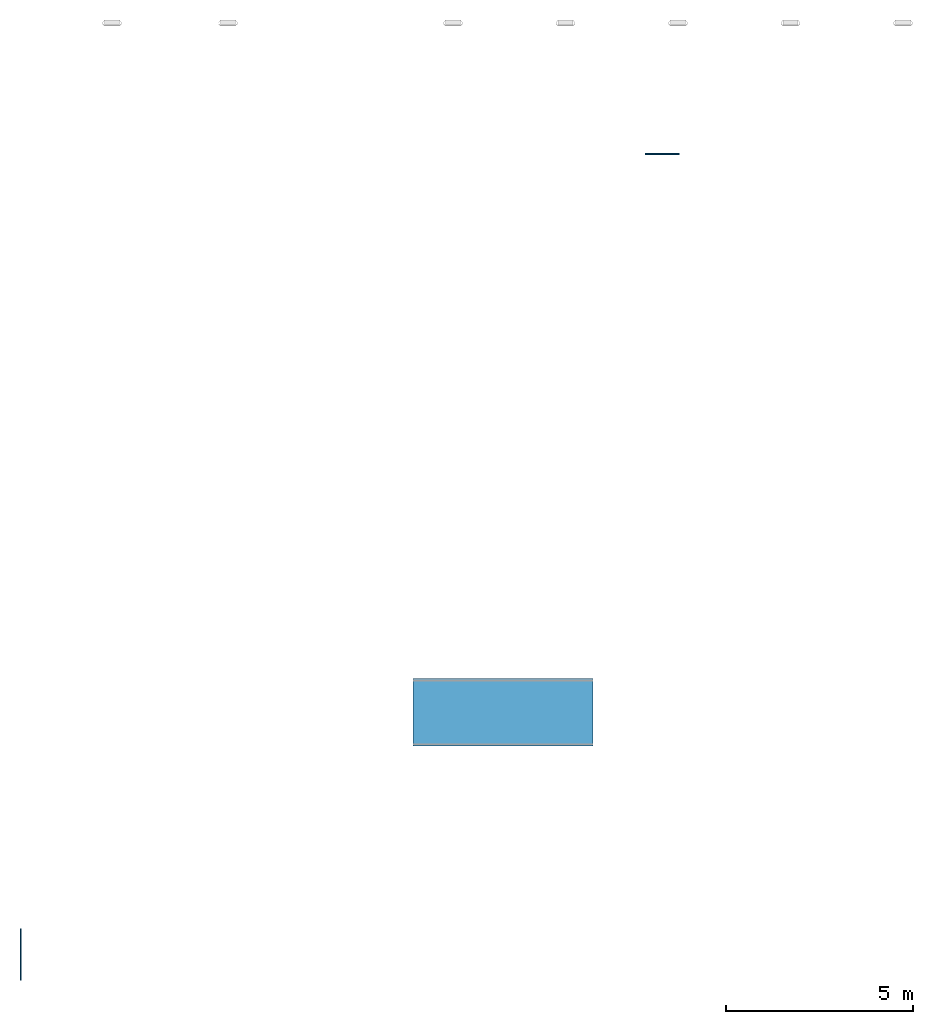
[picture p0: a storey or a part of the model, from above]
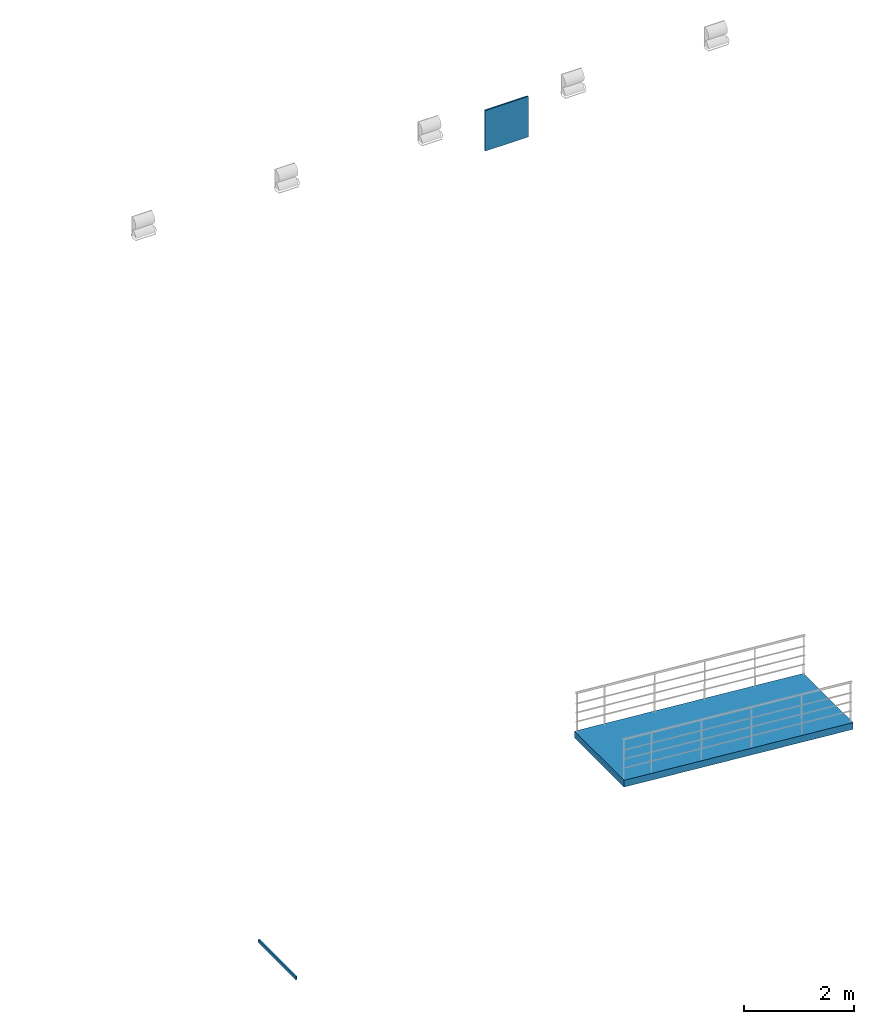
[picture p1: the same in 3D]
Properties of the parts of a building model (IFC2X3), part 1 of 2

# File
Description: ViewDefinition [CoordinationView_V2.0]
File name: 04
Time: 2021-05-14T01:04:37
Written by: The EXPRESS Data Manager Version 5.02.0100.07 : 28 Aug 2013
Made in: 20180216_1515(x64) - Exporter 19.0.0.405 - IU alternativa 19.0.0.405
Comment: STEP Physical File produced by: The EXPRESS Data Manager Version 5.02.0100.07 : 28 Aug 2013 * Module: EDMstepFileFactory/EDMstandAlone * Creation date: Fri May 14 01:04:37 2021 * Host: LAPTOP-GIKO4DUL * Database: C:\Users\MARIAT~1\AppData\Local\Temp\{2545EC60-F883-4820-98E2-E40E6828F80A}\ifc * Database version: 5507 * Database creation date: Fri May 14 01:04:12 2021 * Schema: IFC2X3 * Model: DataRepository.ifc * Model creation date: Fri May 14 01:04:12 2021 * Header model: DataRepository.ifc_HeaderModel * Header model creation date: Fri May 14 01:04:12 2021 * EDMuser: sdai-user * EDMgroup: sdai-group * License ID and type: 5605 : Permanent license. Expiry date: * EDMstepFileFactory options: 020000

# IfcProject, 04
LongName: CURSO REVIT ARCHITECTURE 2015; Phase: Projeto Básico

# IfcSite, Default
RefLatitude: -7, -6, -57, -999999; RefLongitude: -34, -53, -12, -999999; RefElevation: 0 m

# IfcBuilding, C. C. L. Monsenhor Antônio Sampaio
LongName: C. C. L. Monsenhor Antônio Sampaio
Pset_BuildingCommon - NumberOfStoreys: 4

# IfcBuildingStorey (4)
In: C. C. L. Monsenhor Antônio Sampaio
Name | LongName | Elevation (m)
Nível 0 | Nível 0 | -1.18033e-13
Nível 0.8 | Nível 0.8 | 0.8
Nível 1.2 | Nível 1.2 | 1.2
COBERTURA BLOCO 01 | COBERTURA BLOCO 01 | 4.3

# IfcSpace (32)
InteriorOrExteriorSpace: INTERNAL
Name | In | LongName | Reference | CeilingCovering | WallCovering | FloorCovering
57 | Nível 0 | Área | Área 57 | Group: Gross Building
58 | Nível 1.2 | Área | Área 58 | Group: Gross Building
77 | Nível 1.2 | SALA DE AULA 01 | SALA DE AULA 01 77 | 1 | 1 | 1
78 | Nível 1.2 | DIRETORIA | DIRETORIA 78 | 1 | 1 | 1
79 | Nível 1.2 | SECRETARIA | SECRETARIA 79 | 1 | 1 | 1
80 | Nível 1.2 | SALA DE AULA 03 | SALA DE AULA 03 80 | 1 | 1 | 1
81 | Nível 1.2 | SALA DE AULA 04 | SALA DE AULA 04 81 | 1 | 1 | 1
82 | Nível 1.2 | SALA DE AULA 02 | SALA DE AULA 02 82 | 1 | 1 | 1
83 | Nível 1.2 | SALA DE MEDIAÇÃO TECNOLÓGICA | SALA DE MEDIAÇÃO TECNOLÓGICA 83 | 1 | 1 | 2
85 | Nível 1.2 | SALA DE AULA 05 | SALA DE AULA 05 85 | 1 | 1 | 1
86 | Nível 1.2 | BWC FUNC. | BWC FUNC. 86 | 2 | 2 | 1
87 | Nível 1.2 | DML | DML 87 | 2 | 2 | 1
89 | Nível 1.2 | SALA DE INFORMÁTICA | SALA DE INFORMÁTICA 89 | 1 | 1 | 2
90 | Nível 1.2 | COZINHA | COZINHA 90 | 2 | 2 | 1
91 | Nível 1.2 | DEPÓSITO | DEPÓSITO 91 | 2 | 3 | 1
92 | Nível 1.2 | BWC MASC. | BWC MASC. 92 | 2 | 2 | 1
93 | Nível 1.2 | BWC FEM. | BWC FEM. 93 | 2 | 2 | 1
94 | Nível 1.2 | AUDITÓRIO | AUDITÓRIO 94 | 1 | 1 | 2
95 | Nível 1.2 | PCD M. | PCD M. 95 | 2 | 2 | 1
96 | Nível 1.2 | PCD F. | PCD F. 96 | 2 | 2 | 1
98 | Nível 1.2 | BWC M. | BWC M. 98 | 2 | 2 | 1
99 | Nível 1.2 | BWC F. | BWC F. 99 | 2 | 2 | 1
100 | Nível 1.2 | HALL | HALL 100 | 1 | 1 | 1
101 | Nível 1.2 | CIRCULAÇÃO 01 | CIRCULAÇÃO 01 101 | 1 | 1 | 1
102 | Nível 1.2 | CIRC. 02 | CIRC. 02 102 | 1
103 | Nível 1.2 | CIRC. 03 | CIRC. 03 103
104 | Nível 1.2 | PÁTIO ABERTO | PÁTIO ABERTO 104 | 3 | 4
108 | Nível 1.2 | JARDIM | JARDIM 108
110 | Nível 1.2 | LIXO | LIXO 110 | 2 | 2 | 1
116 | Nível 1.2 | HALL AUDITÓRIO | HALL AUDITÓRIO 116
117 | Nível 1.2 | CORREDOR EXTERNO | CORREDOR EXTERNO 117 | 4 | 4
118 | Nível 1.2 | ÁREA EXTERNA | ÁREA EXTERNA 118 | 3 | 4

# IfcBuildingElementProxy: 2000 Litros, Cisterna:2000 Litros:4462246
In: Nível 1.2
Type - Material: Polietileno
Pset_BuildingElementProxyCommon - Reference: 2000 Litros
Pset_ManufacturerTypeInformation - Manufacturer: Fortlev

# IfcBuildingElementProxy: ASYG07-14KMTB (21)
Type - Material: Plastic - Fujitsu General - VR-II - White
Pset_BuildingElementProxyCommon - Reference: ASYG07-14KMTB
Pset_ManufacturerTypeInformation - Manufacturer: FUJITSU GENERAL LIMITED
Name (SPLIT_menor:ASYG07-14KMTB:...) | In
4409967 | 101
4411720 | 79
4411962 | 79
4412251 | 101
4412547 | 101
4412678 | 104
4412776 | 104
4413141 | 101
4413718 | 101
4413755 | 78
4413810 | 78
4413875 | 101
4413943 | 86
4413980 | 117
4414288 | 117
4414644 | 117
4414756 | 117
4414872 | 117
4414974 | 118
4415056 | 118
4460563 | 101

# IfcBuildingElementProxy: Geladeira Inverse Frost Free 422 litros BRE50 - Inox, Geladeira Inverse Frost Free 422 litros BRE50 - Inox:Geladeira Inverse Frost Free 422 litros BRE50 - Inox:4298330
In: 90
Type - Material: Vidro, Inox, Alumínio, Plástico Cinza
Pset_BuildingElementProxyCommon - Reference: Geladeira Inverse Frost Free 422 litros BRE50 - Inox
Pset_ManufacturerTypeInformation - Manufacturer: Brastemp

# IfcBuildingElementProxy: M_Parking Symbol - ADA (2)
In: 94
Material: Paint - White
Pset_BuildingElementProxyCommon - Reference: M_Parking Symbol - ADA
Name (M_Parking Symbol - ADA:M_Parking Symbol - ADA:...)
4352313
4352314

# IfcBuildingElementProxy: Samsung_C8000_UN55C8000_55_3D_LED_10171 (2)
In: 83
Type - Material: Samsung C8000 UN55C8000 55"_LOGO, Samsung C8000 UN55C8000 55"_METAL, Samsung C8000 UN55C8000 55"_FIBERGLASS, Samsung C8000 UN55C8000 55"_SCREEN
Pset_BuildingElementProxyCommon - Reference: Samsung_C8000_UN55C8000_55_3D_LED_10171
Name (Samsung_C8000_UN55C8000_55_3D_LED_10171:Samsung_C8000_UN55C8000_55_3D_LED_10171:...)
4340818
4340819

# IfcBuildingElementProxy: Texto do modelo:280mm Arial
In: COBERTURA BLOCO 01
Pset_BuildingElementProxyCommon - Reference: 280mm Arial

# IfcBuildingElementProxy: Árvore menor - 3 metros (3)
In: Nível 1.2
Pset_BuildingElementProxyCommon - Reference: Árvore menor - 3 metros
Name (RPC Árvore - Tropical:Árvore menor - 3 metros:...)
4311700
4314249
4314272

# IfcColumn: d. 20cm (6)
In: Nível 1.2
Type - ElementType: d. 20cm; PredefinedType: COLUMN
Pset_ColumnCommon - IsExternal: no; Reference: d. 20cm; LoadBearing: yes
Name (Pilar circular:d. 20cm:...)
4174025 | Pset_ColumnCommon - Slope: 0 deg
4174095 | Pset_ColumnCommon - Slope: 0 deg
4174138
4174175
4174350
4174637

# IfcCovering: Forro composto:Forro Mineral (3)
PredefinedType: CEILING; Material: .Forro em gesso 0.03 m
Pset_CoveringCommon - Reference: Forro Mineral; TotalThickness: 0.03 m
Name (Forro composto:Forro Mineral:...) | In
4361125 | 83
4361229 | 89
4361289 | 94

# IfcCovering: Forro composto:Forro de Gesso (20)
PredefinedType: CEILING; Material: .Placa de Gesso Pintada de Branco 0.03 m
Pset_CoveringCommon - Reference: Forro de Gesso; TotalThickness: 0.03 m
Name (Forro composto:Forro de Gesso:...) | In
4361105 | 77
4361117 | 82
4361133 | 78
4361141 | 79
4361189 | 80
4361197 | 81
4361213 | 85
4361237 | 90
4361245 | 91
4361253 | 92
4361263 | 95
4361271 | 93
4361281 | 96
4361297 | 98
4361305 | 99
4361413 | 87
4361421 | 86
4361437 | Nível 1.2
4361453 | Nível 1.2
4399040 | 110

# IfcDoor: 90 x 211 AZUL (21)
Type - ParameterTakesPrecedence: no; Sizeable: no; Material: Pintura Azul
OverallHeight: 2.1 m; OverallWidth: 0.9 m
Pset_DoorCommon - IsExternal: no; Reference: 90 x 211 AZUL; ThermalTransmittance: 3.7021 kg/K/s3
Name (Porta levantamento:90 x 211 AZUL:...) | In
4220187 | Nível 1.2
4220721 | Nível 1.2
4221403 | Nível 1.2
4221503 | Nível 1.2
4222283 | Nível 1.2
4222623 | Nível 1.2
4223136 | Nível 1.2
4224336 | Nível 1.2
4224835 | Nível 1.2
4224943 | Nível 1.2
4225145 | Nível 1.2
4225239 | Nível 1.2
4225373 | Nível 1.2
4225458 | Nível 1.2
4225538 | Nível 1.2
4225822 | Nível 1.2
4307124 | Nível 1.2
4307657 | Nível 1.2
4353306 | Nível 1.2
4400503 | Nível 0.8
4400869 | Nível 0.8

# IfcDoor: AUDITÓRIO azul, Porta dupla auditorio:AUDITÓRIO azul:3969656
In: Nível 1.2
Type - ParameterTakesPrecedence: no; Sizeable: no; Material: Pintura Azul, .Vidro transparente, door panel
OverallHeight: 2.05 m; OverallWidth: 1.85 m
Pset_DoorCommon - IsExternal: no; Reference: AUDITÓRIO azul

# IfcDoor: LIXEIRA E CASA DE GÁS (2)
In: Nível 1.2
Type - ParameterTakesPrecedence: no; Sizeable: no; Material: Alumínio - Pintura eletrostática branca
OverallHeight: 2.16 m; OverallWidth: 0.88 m
Pset_DoorCommon - IsExternal: no; Reference: LIXEIRA E CASA DE GÁS
Pset_ManufacturerTypeInformation - Manufacturer: Sasazaki
Name (Porta de abrir com veneziana ventilada - PAVV:LIXEIRA E CASA DE GÁS:...)
4394019
4396577

# IfcDoor: PORTA BOXE BANHEIROS (3)
In: Nível 1.2
Type - OperationType: SINGLE_SWING_LEFT; ParameterTakesPrecedence: no; Sizeable: no; Classification: 05.01.050 (Uniformat); Material: Padrão, .Madeira, Alumínio
Type - Porta 60x165-15:PORTA BOXE BANHEIROS:4277022 - PanelOperation: SWINGING
OverallHeight: 1.8 m; OverallWidth: 0.744793 m
Pset_DoorCommon - IsExternal: no; Reference: PORTA BOXE BANHEIROS
Name (Porta 60x165-15:PORTA BOXE BANHEIROS:...)
4277022
4277023
4277024

# IfcDoor: PORTA BOXE BANHEIROS (3)
In: Nível 1.2
Type - OperationType: SINGLE_SWING_RIGHT; ParameterTakesPrecedence: no; Sizeable: no; Classification: 05.01.050 (Uniformat); Material: Padrão, .Madeira, Alumínio
Type - Porta 60x165-15:PORTA BOXE BANHEIROS:4276989 - PanelOperation: SWINGING
OverallHeight: 1.8 m; OverallWidth: 0.744793 m
Pset_DoorCommon - IsExternal: no; Reference: PORTA BOXE BANHEIROS
Name (Porta 60x165-15:PORTA BOXE BANHEIROS:...)
4276989
4276990
4276991

# IfcDoor: PORTA DE ENTRADA 3m, Porta pivotante dupla sem revestimento:PORTA DE ENTRADA 3m:3965441
In: Nível 1.2
Type - ParameterTakesPrecedence: no; Sizeable: no; Material: .Alumínio Azul
OverallHeight: 3.1 m; OverallWidth: 1.4 m
Pset_DoorCommon - Reference: PORTA DE ENTRADA 3m; IsExternal: yes; ThermalTransmittance: 3.7021 kg/K/s3

# IfcFlowTerminal: 1994.C.CT_Cromado CR10, Chuveiro:1994.C.CT_Cromado CR10:4299063
In: 86
Classification: D2020 Domestic Water Distribution (Uniformat); Material: Deca CR10 Cromado Metal
Pset_ManufacturerTypeInformation - Manufacturer: Deca
Pset_DistributionFlowElementCommon - Reference: 1994.C.CT_Cromado CR10

# IfcFlowTerminal: 455 x 360 x 850mm (2)
In: 100
Pset_DistributionFlowElementCommon - Reference: 455 x 360 x 850mm
Name (Pia de parede:455 x 360 x 850mm:...)
4408259
4419486

# IfcFlowTerminal: ANMX309 (10)
Type - PredefinedType: SANITARYFOUNTAIN; Material: Aço inoxidável, escovado
Pset_ManufacturerTypeInformation - ModelReference: Drinking Fountain_ANMX309; Manufacturer: ws-info.uk@franke.com
Pset_DistributionFlowElementCommon - Reference: ANMX309
Name (NBS_FrankeSissonsLtd_DrnkngFntnPckgs_DrinkingFountain_ANMX309:ANMX309:...) | In
4391114 | 101
4391115 | 101
4391116 | 101
4393749 | 103
4393750 | 103
4393751 | 103
4393813 | 103
4393814 | 103
4393815 | 103
4393923 | 101

# IfcFlowTerminal: Assento para Bacia Sanitária (9)
Classification: D2010110 Water Closets - Single (Uniformat); Material: Deca GE17 Branco Gelo Plástico
Pset_ManufacturerTypeInformation - Manufacturer: Deca
Pset_DistributionFlowElementCommon - Reference: Assento para Bacia Sanitária
Name (Assento para Bacia Sanitária:Assento para Bacia Sanitária:...) | In
4280281 | 92
4280360 | 92
4280666 | 92
4281077 | 93
4281081 | 93
4281084 | 93
4299518 | 86
4305914 | 99
4307576 | 98

# IfcFlowTerminal: BCS460 W16L124 1xLED24/840 MLO-PC (76)
Type - Material: glass - blue - t85, metal - aluminium
Pset_ManufacturerTypeInformation - Manufacturer: Philips
Pset_DistributionFlowElementCommon - Reference: BCS460 W16L124 1xLED24/840 MLO-PC
Name (63_PHILIPS_smartform-LED-surface_f:BCS460 W16L124 1xLED24/840 MLO-PC:...) | In
4367687 | 81
4367688 | 81
4367689 | 81
4367690 | 81
4370990 | 81
4370991 | 81
4371206 | 80
4371207 | 80
4371208 | 80
4371209 | 80
4371211 | 80
4371212 | 80
4371623 | 77
4371624 | 77
4371625 | 77
4371626 | 77
4371627 | 77
4371628 | 77
4371737 | 82
4371738 | 82
4371739 | 82
4371740 | 82
4371742 | 82
4371743 | 82
4371914 | 83
4371915 | 83
4371916 | 83
4371917 | 83
4371918 | 83
4371919 | 83
4372436 | 89
4372437 | 89
4372438 | 89
4372439 | 89
4372440 | 89
4372441 | 89
4372748 | 90
4372749 | 90
4372750 | 90
4373002 | 94
4373003 | 94
4373210 | 94
4373211 | 94
4373272 | 94
4373273 | 94
4373290 | 94
4373291 | 94
4373303 | 94
4373304 | 94
4373317 | 94
4373318 | 94
4373326 | 94
4373327 | 94
4373403 | Nível 1.2
4373404 | Nível 1.2
4373625 | 85
4373628 | 85
4373744 | 85
4373745 | 85
4387714 | 100
4387939 | 101
4388071 | 101
4388201 | 101
4388233 | 101
4388684 | 92
4388706 | 93
4389699 | 92
4389745 | 93
4390718 | 103
4390791 | 103
4390823 | 103
4390860 | 102
4390928 | 102
4391031 | 102
4398995 | 102
4398996 | 102

# IfcFlowTerminal: BR03_ConjuntoLavatórioeBaciaAcessíveis_ComVálvulaDeDescarga_DN32mm(1 1/4") (2)
Classification: 08.16.091 (Uniformat); Material: FDE_AçoCromado, FDE_CerâmicaEsmaltadaBranca, FDE_ResinaPosliéster (Branco), FDE_AçoInox
Pset_DistributionFlowElementCommon - Reference: BR03_ConjuntoLavatórioeBaciaAcessíveis_ComVálvulaDeDescarga_DN32mm(1 1/4")
Name (FDE_BR03_ConjuntoLavatórioeBaciaAcessíveis:BR03_ConjuntoLavatórioeBaciaAcessíveis_ComVálvulaDeDescarga_DN32mm(1 1/4"):...) | In
4292054 | 95
4293119 | 96

# IfcFlowTerminal: CT.25_Branco Gelo GE17, Deca_Shared_Coluna para Tanque_TQ.03:CT.25_Branco Gelo GE17:4334062
In: Nível 1.2
Classification: D2010400 Sinks (Uniformat); Material: Deca GE17 Branco Gelo Cerâmica
Pset_ManufacturerTypeInformation - Manufacturer: Deca
Pset_DistributionFlowElementCommon - Reference: CT.25_Branco Gelo GE17

# IfcFlowTerminal: Caixa de Descarga Acoplada (9)
Classification: D2010110 Water Closets - Single (Uniformat); Material: Deca CR37 Creme Cerâmica
Pset_ManufacturerTypeInformation - Manufacturer: CD.00.17
Pset_DistributionFlowElementCommon - Reference: Caixa de Descarga Acoplada
Name (Caixa de Descarga Acoplada:Caixa de Descarga Acoplada:...) | In
4280282 | 92
4280361 | 92
4280667 | 92
4281078 | 93
4281082 | 93
4281085 | 93
4299519 | 86
4305915 | 99
4307577 | 98

# IfcFlowTerminal: Cuba 40x70 (2)
In: 90
Material: Stainless Steel
Pset_ManufacturerTypeInformation - Manufacturer: CABRO
Pset_DistributionFlowElementCommon - Reference: Cuba 40x70
Name (Cuba_Cozinha1:Cuba 40x70:...)
4297387
4297388

# IfcFlowTerminal: H613_RestritorDeVazãoPara6L/minTorneiraseMisturadores (2)
Classification: 08.17.078 (Uniformat)
Pset_DistributionFlowElementCommon - Reference: H613_RestritorDeVazãoPara6L/minTorneiraseMisturadores
Name (FDE_H613_DispositivosRestritoresDeVazão:H613_RestritorDeVazãoPara6L/minTorneiraseMisturadores:...) | In
4292057 | 95
4293122 | 96

# IfcFlowTerminal: IL63_4x16W-40x40 (10)
In: Nível 1.2
Type - Classification: 09.09.063 (Uniformat); Material: Aço com Acabamento em Pintura Eletrostática em Pó Branca, Lâmpada Fluorescente, Policarbonato, Alumínio Anodizado Polido
Pset_DistributionFlowElementCommon - Reference: IL63_4x16W-40x40
Name (FDE_IL63_LumináriaInterna_LumináriadeEmbutir_comRefletoreAletas:IL63_4x16W-40x40:...)
4386625
4386684
4386753
4386830
4386903
4386990
4387107
4387216
4387559
4399196

# IfcFlowTerminal: IL84_1x150W_opção1 (2)
Type - Classification: 09.11.076 (Uniformat); Material: Alumínio Anodizado Brilhante, Lâmpada de Vapor de Sódio, Porcelana, Vidro Temperado, Aço galvanizado
Pset_DistributionFlowElementCommon - Reference: IL84_1x150W_opção1
Name (FDE_IL84_LumináriaExterna_Projetor_opção1:IL84_1x150W_opção1:...) | In
4402668 | 108
4408045 | Nível 1.2

# IfcFlowTerminal: IL85_1x250W_opção2 (7)
In: Nível 0
Type - Classification: 09.11.077 (Uniformat); Material: Lâmpada de Vapor de Sódio, Porcelana, Alumínio Anodizado Brilhante, Vidro Temperado, Aço galvanizado
Pset_DistributionFlowElementCommon - Reference: IL85_1x250W_opção2
Name (FDE_IL85_LumináriaExterna_Projetor_opção2:IL85_1x250W_opção2:...)
4403228
4403448
4403821
4403822
4403885
4403909
4403936

# IfcFlowTerminal: L.37.17_Branco Gelo GE17 (9)
Classification: D2010400 Sinks (Uniformat); Material: Deca GE17 Branco Gelo Cerâmica
Pset_ManufacturerTypeInformation - Manufacturer: Deca
Pset_DistributionFlowElementCommon - Reference: L.37.17_Branco Gelo GE17
Name (Cuba Oval de Embutir1:L.37.17_Branco Gelo GE17:...) | In
4277048 | 93
4277050 | 93
4277202 | 93
4277747 | 92
4277749 | 92
4277750 | 92
4300827 | 86
4304887 | 99
4307573 | 98

# IfcFlowTerminal: Lavatório Top (6)
Material: Cromado - Docol
Pset_ManufacturerTypeInformation - Manufacturer: Docol
Pset_DistributionFlowElementCommon - Reference: Lavatório Top
Name (Sifao para lavatorio - DocolBasicos:Lavatório Top:...) | In
4277647 | 93
4277701 | 93
4277722 | 93
4277751 | 92
4277752 | 92
4277753 | 92

# IfcFlowTerminal: P.750_Creme CR37_Acionamento Simples 6lpf (9)
Classification: D2010110 Water Closets - Single (Uniformat); Material: Deca CR37 Creme Cerâmica
Pset_ManufacturerTypeInformation - Manufacturer: Deca
Pset_DistributionFlowElementCommon - Reference: P.750_Creme CR37_Acionamento Simples 6lpf
Name (Bacia para Caixa Acoplada:P.750_Creme CR37_Acionamento Simples 6lpf:...) | In
4280279 | 92
4280358 | 92
4280664 | 92
4281076 | 93
4281080 | 93
4281083 | 93
4299516 | 86
4305912 | 99
4307575 | 98

# IfcFlowTerminal: Poste de iluminação - Redondo (18)
Type - Material: Metal - Cromo, Vidro, Branco, Alta Luminosidade, Metal - Alum
Pset_DistributionFlowElementCommon - Reference: Poste de iluminação - Redondo
Name (Poste de iluminação - Redondo:Poste de iluminação - Redondo:...) | In
4399500 | 104
4401171 | 104
4404501 | 104
4404594 | 104
4405208 | 104
4405645 | 104
4406009 | 118
4406144 | 118
4407786 | 118
4408570 | 117
4408571 | 117
4408572 | 117
4408573 | 117
4408574 | 117
4408575 | 117
4408576 | 117
4408577 | 117
4408923 | 104

# IfcFlowTerminal: TQ.03_Branco Gelo GE17, Deca_Tanque_TQ.03_40 Litros:TQ.03_Branco Gelo GE17:4334060
In: Nível 1.2
Classification: D2010400 Sinks (Uniformat); Material: Deca GE17 Branco Gelo Cerâmica
Pset_ManufacturerTypeInformation - Manufacturer: Deca
Pset_DistributionFlowElementCommon - Reference: TQ.03_Branco Gelo GE17

# IfcFlowTerminal: Torneira 1 (4)
In: 100
Pset_DistributionFlowElementCommon - Reference: Torneira 1
Name (Torneira 1:Torneira 1:...)
4408260
4408261
4419487
4419488

# IfcFlowTerminal: Torneira 3 (2)
In: 100
Pset_DistributionFlowElementCommon - Reference: Torneira 3
Name (Torneira 3:Torneira 3:...)
4408262
4419489

# IfcFurnishingElement: 5-M-SR11-00-E111-A2B-F10001/F193 (5)
Type - ElementType: 5-M-SR11-00-E111-A2B-F10001/F193; Material: Nylon Black, Mesh Black, Black, Silver
Pset_ManufacturerTypeInformation - Manufacturer: Modernform
Name (Cadeira diretoria:5-M-SR11-00-E111-A2B-F10001/F193:...) | In
4348319 | 78
4352126 | 94
4352128 | 94
4352129 | 94
4352130 | 94

# IfcFurnishingElement: 800x800mm, NBS_OffcTbls_RoundTable:800x800mm:4348874
In: 79
Type - ElementType: 800x800mm; Material: Wood - Glue-Laminated
Pset_ManufacturerTypeInformation - ModelReference: Round Table; Manufacturer: info@theNBS.com

# IfcFurnishingElement: Bancada (8)
Type - ElementType: Bancada
Name | In | Group
BancadaL:Bancada:4297389 | 90
Bancada_balcao:Bancada:4345387 | 89 | Grupo de modelos:Bancada Informática:4345391
Bancada_balcao:Bancada:4345395 | 89 | Grupo de modelos:Bancada Informática:4345399
Bancada_balcao:Bancada:4345403 | 89 | Grupo de modelos:Bancada Informática:4345407
Bancada_balcao:Bancada:4345411 | 89 | Grupo de modelos:Bancada Informática:4345415
Bancada_balcao:Bancada:4345419 | 89 | Grupo de modelos:Bancada Informática:4345423
Bancada_balcao:Bancada:4345427 | 89 | Grupo de modelos:Bancada Informática:4345431
Bancada_balcao:Bancada:4345435 | 89 | Grupo de modelos:Bancada Informática:4345439

# IfcFurnishingElement: Bancada_50x320 2 (3)
Type - ElementType: Bancada_50x320 2
Name (Bancada1:Bancada_50x320 2:...) | In
4300014 | 86
4304886 | 99
4307572 | 98

# IfcFurnishingElement: Bancada_L_60x265 (3)
Type - ElementType: Bancada_L_60x265
Name (Bancada1:Bancada_L_60x265:...) | In
4277047 | 93
4277746 | 92
4297386 | 90

# IfcFurnishingElement: Cadeira auditório (90)
In: 94
Type - ElementType: Cadeira auditório; Material: V9 - V9 - Ecopelle_672_658, V9 - V9 - RAL_9006_Grigio
Name
Furniture_Armchairs_Ares-Line_V9:Cadeira auditório:4352305
cadeira auditório pcd:Cadeira auditório:4352309
cadeira auditório pcd:Cadeira auditório:4352310
cadeira auditório pcd:Cadeira auditório:4352311
cadeira auditório pcd:Cadeira auditório:4352315
cadeira auditório pcd:Cadeira auditório:4352316
cadeira auditório pcd:Cadeira auditório:4352317
cadeira auditório pcd:Cadeira auditório:4352318
cadeira auditório pcd:Cadeira auditório:4352430
cadeira auditório pcd:Cadeira auditório:4352431
cadeira auditório pcd:Cadeira auditório:4352516
cadeira auditório pcd:Cadeira auditório:4352517
cadeira auditório pcd:Cadeira auditório:4352527
cadeira auditório pcd:Cadeira auditório:4352528
cadeira auditório pcd:Cadeira auditório:4352529
cadeira auditório pcd:Cadeira auditório:4352530
cadeira auditório pcd:Cadeira auditório:4352531
cadeira auditório pcd:Cadeira auditório:4352532
cadeira auditório pcd:Cadeira auditório:4352972
cadeira auditório pcd:Cadeira auditório:4352973
cadeira auditório pcd:Cadeira auditório:4352974
cadeira auditório pcd:Cadeira auditório:4352975
cadeira auditório pcd:Cadeira auditório:4352976
cadeira auditório pcd:Cadeira auditório:4352977
cadeira auditório pcd:Cadeira auditório:4352978
cadeira auditório pcd:Cadeira auditório:4352979
cadeira auditório pcd:Cadeira auditório:4352980
cadeira auditório pcd:Cadeira auditório:4352981
cadeira auditório pcd:Cadeira auditório:4352982
cadeira auditório pcd:Cadeira auditório:4352983
cadeira auditório pcd:Cadeira auditório:4353070
cadeira auditório pcd:Cadeira auditório:4353071
cadeira auditório pcd:Cadeira auditório:4353072
cadeira auditório pcd:Cadeira auditório:4353073
cadeira auditório pcd:Cadeira auditório:4353074
cadeira auditório pcd:Cadeira auditório:4353075
cadeira auditório pcd:Cadeira auditório:4353076
cadeira auditório pcd:Cadeira auditório:4353077
cadeira auditório pcd:Cadeira auditório:4353078
cadeira auditório pcd:Cadeira auditório:4353079
cadeira auditório pcd:Cadeira auditório:4353080
cadeira auditório pcd:Cadeira auditório:4353081
cadeira auditório pcd:Cadeira auditório:4353100
cadeira auditório pcd:Cadeira auditório:4353101
cadeira auditório pcd:Cadeira auditório:4353102
cadeira auditório pcd:Cadeira auditório:4353103
cadeira auditório pcd:Cadeira auditório:4353104
cadeira auditório pcd:Cadeira auditório:4353105
cadeira auditório pcd:Cadeira auditório:4353106
cadeira auditório pcd:Cadeira auditório:4353107
cadeira auditório pcd:Cadeira auditório:4353108
cadeira auditório pcd:Cadeira auditório:4353109
cadeira auditório pcd:Cadeira auditório:4353110
cadeira auditório pcd:Cadeira auditório:4353111
cadeira auditório pcd:Cadeira auditório:4353119
cadeira auditório pcd:Cadeira auditório:4353120
cadeira auditório pcd:Cadeira auditório:4353121
cadeira auditório pcd:Cadeira auditório:4353122
cadeira auditório pcd:Cadeira auditório:4353123
cadeira auditório pcd:Cadeira auditório:4353124
cadeira auditório pcd:Cadeira auditório:4353125
cadeira auditório pcd:Cadeira auditório:4353126
cadeira auditório pcd:Cadeira auditório:4353127
cadeira auditório pcd:Cadeira auditório:4353128
cadeira auditório pcd:Cadeira auditório:4353129
cadeira auditório pcd:Cadeira auditório:4353130
cadeira auditório pcd:Cadeira auditório:4353151
cadeira auditório pcd:Cadeira auditório:4353152
cadeira auditório pcd:Cadeira auditório:4353153
cadeira auditório pcd:Cadeira auditório:4353154
cadeira auditório pcd:Cadeira auditório:4353155
cadeira auditório pcd:Cadeira auditório:4353156
cadeira auditório pcd:Cadeira auditório:4353157
cadeira auditório pcd:Cadeira auditório:4353158
cadeira auditório pcd:Cadeira auditório:4353159
cadeira auditório pcd:Cadeira auditório:4353160
cadeira auditório pcd:Cadeira auditório:4353161
cadeira auditório pcd:Cadeira auditório:4353162
cadeira auditório pcd:Cadeira auditório:4353172
cadeira auditório pcd:Cadeira auditório:4353173
cadeira auditório pcd:Cadeira auditório:4353174
cadeira auditório pcd:Cadeira auditório:4353175
cadeira auditório pcd:Cadeira auditório:4353176
cadeira auditório pcd:Cadeira auditório:4353177
cadeira auditório pcd:Cadeira auditório:4353178
cadeira auditório pcd:Cadeira auditório:4353179
cadeira auditório pcd:Cadeira auditório:4353180
cadeira auditório pcd:Cadeira auditório:4353181
cadeira auditório pcd:Cadeira auditório:4353182
cadeira auditório pcd:Cadeira auditório:4353183

# IfcFurnishingElement: Cadeira-Breuer (15)
Type - ElementType: Cadeira-Breuer; Material: Tecido - Fibras de bambu, Metal - Cromo
Name | In
Cadeira-Breuer1:Cadeira-Breuer:4339522 | 77
Cadeira-Breuer1:Cadeira-Breuer:4340231 | 80
Cadeira-Breuer1:Cadeira-Breuer:4340532 | 81
Cadeira-Breuer1:Cadeira-Breuer:4340592 | 82
Cadeira-Breuer1:Cadeira-Breuer:4345440 | 89
Cadeira-Breuer1:Cadeira-Breuer:4348317 | 78
Cadeira-Breuer1:Cadeira-Breuer:4348318 | 78
Cadeira-Breuer1:Cadeira-Breuer:4348547 | 79
Cadeira-Breuer1:Cadeira-Breuer:4348549 | 79
Cadeira-Breuer1:Cadeira-Breuer:4348875 | 79
Cadeira-Breuer1:Cadeira-Breuer:4348876 | 79
Cadeira-Breuer1:Cadeira-Breuer:4348877 | 79
Cadeira-Breuer1:Cadeira-Breuer:4348878 | 79
Cadeira-Breuer1:Cadeira-Breuer:4349871 | 85
Cadeira-Breuer:Cadeira-Breuer:4418807 | Nível 0.8

# IfcFurnishingElement: Carteira_Sala de Aula (140)
Type - ElementType: Carteira_Sala de Aula; Classification: E2020200 Furniture & Accessories (Uniformat); Material: Furniture - KI - Chair Glide, Furniture - KI - Chair Frame, Furniture - KI - Tablet, Furniture - KI - Chair Poly
Pset_ManufacturerTypeInformation - Manufacturer: KI
Name (Tablet_Arm_Chair_4-Leg-KI-Strive:Carteira_Sala de Aula:...) | In | Group
4339220 | 77 | Grupo de modelos:CARTEIRAS 2:4339250
4339221 | 77 | Grupo de modelos:CARTEIRAS 2:4339250
4339222 | 77 | Grupo de modelos:CARTEIRAS 2:4339250
4339223 | 77 | Grupo de modelos:CARTEIRAS 2:4339250
4339224 | 77 | Grupo de modelos:CARTEIRAS 2:4339250
4339225 | 77 | Grupo de modelos:CARTEIRAS 2:4339250
4339226 | 77 | Grupo de modelos:CARTEIRAS 2:4339250
4339227 | 77 | Grupo de modelos:CARTEIRAS 2:4339250
4339228 | 77 | Grupo de modelos:CARTEIRAS 2:4339250
4339229 | 77 | Grupo de modelos:CARTEIRAS 2:4339250
4339230 | 77 | Grupo de modelos:CARTEIRAS 2:4339250
4339231 | 77 | Grupo de modelos:CARTEIRAS 2:4339250
4339232 | 77 | Grupo de modelos:CARTEIRAS 2:4339250
4339233 | 77 | Grupo de modelos:CARTEIRAS 2:4339250
4339234 | 77 | Grupo de modelos:CARTEIRAS 2:4339250
4339235 | 77 | Grupo de modelos:CARTEIRAS 2:4339250
4339236 | 77 | Grupo de modelos:CARTEIRAS 2:4339250
4339237 | 77 | Grupo de modelos:CARTEIRAS 2:4339250
4339238 | 77 | Grupo de modelos:CARTEIRAS 2:4339250
4339239 | 77 | Grupo de modelos:CARTEIRAS 2:4339250
4339240 | 77 | Grupo de modelos:CARTEIRAS 2:4339250
4339241 | 77 | Grupo de modelos:CARTEIRAS 2:4339250
4339242 | 77 | Grupo de modelos:CARTEIRAS 2:4339250
4339243 | 77 | Grupo de modelos:CARTEIRAS 2:4339250
4340206 | 80 | Grupo de modelos:CARTEIRAS 2:4340230
4340207 | 80 | Grupo de modelos:CARTEIRAS 2:4340230
4340208 | 80 | Grupo de modelos:CARTEIRAS 2:4340230
4340209 | 80 | Grupo de modelos:CARTEIRAS 2:4340230
4340210 | 80 | Grupo de modelos:CARTEIRAS 2:4340230
4340211 | 80 | Grupo de modelos:CARTEIRAS 2:4340230
4340212 | 80 | Grupo de modelos:CARTEIRAS 2:4340230
4340213 | 80 | Grupo de modelos:CARTEIRAS 2:4340230
4340214 | 80 | Grupo de modelos:CARTEIRAS 2:4340230
4340215 | 80 | Grupo de modelos:CARTEIRAS 2:4340230
4340216 | 80 | Grupo de modelos:CARTEIRAS 2:4340230
4340217 | 80 | Grupo de modelos:CARTEIRAS 2:4340230
4340218 | 80 | Grupo de modelos:CARTEIRAS 2:4340230
4340219 | 80 | Grupo de modelos:CARTEIRAS 2:4340230
4340220 | 80 | Grupo de modelos:CARTEIRAS 2:4340230
4340221 | 80 | Grupo de modelos:CARTEIRAS 2:4340230
4340222 | 80 | Grupo de modelos:CARTEIRAS 2:4340230
4340223 | 80 | Grupo de modelos:CARTEIRAS 2:4340230
4340224 | 80 | Grupo de modelos:CARTEIRAS 2:4340230
4340225 | 80 | Grupo de modelos:CARTEIRAS 2:4340230
4340226 | 80 | Grupo de modelos:CARTEIRAS 2:4340230
4340227 | 80 | Grupo de modelos:CARTEIRAS 2:4340230
4340228 | 80 | Grupo de modelos:CARTEIRAS 2:4340230
4340229 | 80 | Grupo de modelos:CARTEIRAS 2:4340230
4340249 | 81 | Grupo de modelos:CARTEIRAS 2:4340273
4340250 | 81 | Grupo de modelos:CARTEIRAS 2:4340273
4340251 | 81 | Grupo de modelos:CARTEIRAS 2:4340273
4340252 | 81 | Grupo de modelos:CARTEIRAS 2:4340273
4340253 | 81 | Grupo de modelos:CARTEIRAS 2:4340273
4340254 | 81 | Grupo de modelos:CARTEIRAS 2:4340273
4340255 | 81 | Grupo de modelos:CARTEIRAS 2:4340273
4340256 | 81 | Grupo de modelos:CARTEIRAS 2:4340273
4340257 | 81 | Grupo de modelos:CARTEIRAS 2:4340273
4340258 | 81 | Grupo de modelos:CARTEIRAS 2:4340273
4340259 | 81 | Grupo de modelos:CARTEIRAS 2:4340273
4340260 | 81 | Grupo de modelos:CARTEIRAS 2:4340273
4340261 | 81 | Grupo de modelos:CARTEIRAS 2:4340273
4340262 | 81 | Grupo de modelos:CARTEIRAS 2:4340273
4340263 | 81 | Grupo de modelos:CARTEIRAS 2:4340273
4340264 | 81 | Grupo de modelos:CARTEIRAS 2:4340273
4340265 | 81 | Grupo de modelos:CARTEIRAS 2:4340273
4340266 | 81 | Grupo de modelos:CARTEIRAS 2:4340273
4340267 | 81 | Grupo de modelos:CARTEIRAS 2:4340273
4340268 | 81 | Grupo de modelos:CARTEIRAS 2:4340273
4340269 | 81 | Grupo de modelos:CARTEIRAS 2:4340273
4340270 | 81 | Grupo de modelos:CARTEIRAS 2:4340273
4340271 | 81 | Grupo de modelos:CARTEIRAS 2:4340273
4340272 | 81 | Grupo de modelos:CARTEIRAS 2:4340273
4340567 | 82 | Grupo de modelos:CARTEIRAS 2:4340591
4340568 | 82 | Grupo de modelos:CARTEIRAS 2:4340591
4340569 | 82 | Grupo de modelos:CARTEIRAS 2:4340591
4340570 | 82 | Grupo de modelos:CARTEIRAS 2:4340591
4340571 | 82 | Grupo de modelos:CARTEIRAS 2:4340591
4340572 | 82 | Grupo de modelos:CARTEIRAS 2:4340591
4340573 | 82 | Grupo de modelos:CARTEIRAS 2:4340591
4340574 | 82 | Grupo de modelos:CARTEIRAS 2:4340591
4340575 | 82 | Grupo de modelos:CARTEIRAS 2:4340591
4340576 | 82 | Grupo de modelos:CARTEIRAS 2:4340591
4340577 | 82 | Grupo de modelos:CARTEIRAS 2:4340591
4340578 | 82 | Grupo de modelos:CARTEIRAS 2:4340591
4340579 | 82 | Grupo de modelos:CARTEIRAS 2:4340591
4340580 | 82 | Grupo de modelos:CARTEIRAS 2:4340591
4340581 | 82 | Grupo de modelos:CARTEIRAS 2:4340591
4340582 | 82 | Grupo de modelos:CARTEIRAS 2:4340591
4340583 | 82 | Grupo de modelos:CARTEIRAS 2:4340591
4340584 | 82 | Grupo de modelos:CARTEIRAS 2:4340591
4340585 | 82 | Grupo de modelos:CARTEIRAS 2:4340591
4340586 | 82 | Grupo de modelos:CARTEIRAS 2:4340591
4340587 | 82 | Grupo de modelos:CARTEIRAS 2:4340591
4340588 | 82 | Grupo de modelos:CARTEIRAS 2:4340591
4340589 | 82 | Grupo de modelos:CARTEIRAS 2:4340591
4340590 | 82 | Grupo de modelos:CARTEIRAS 2:4340591
4349847 | 85
4349848 | 85
4349849 | 85
4349850 | 85
4349853 | 85
4349854 | 85
4349855 | 85
4349856 | 85
4349860 | 85
4349861 | 85
4349862 | 85
4349866 | 85
4349867 | 85
4349868 | 85
4352042 | 85
4352043 | 85
4352044 | 85
4353527 | 85
4353528 | 85
4353529 | 85
4400800 | 83 | Grupo de modelos:CARTEIRAS 2:4400773
4400801 | 83 | Grupo de modelos:CARTEIRAS 2:4400773
4400802 | 83 | Grupo de modelos:CARTEIRAS 2:4400773
4400803 | 83 | Grupo de modelos:CARTEIRAS 2:4400773
4400804 | 83 | Grupo de modelos:CARTEIRAS 2:4400773
4400805 | 83 | Grupo de modelos:CARTEIRAS 2:4400773
4400806 | 83 | Grupo de modelos:CARTEIRAS 2:4400773
4400807 | 83 | Grupo de modelos:CARTEIRAS 2:4400773
4400808 | 83 | Grupo de modelos:CARTEIRAS 2:4400773
4400809 | 83 | Grupo de modelos:CARTEIRAS 2:4400773
4400810 | 83 | Grupo de modelos:CARTEIRAS 2:4400773
4400811 | 83 | Grupo de modelos:CARTEIRAS 2:4400773
4400812 | 83 | Grupo de modelos:CARTEIRAS 2:4400773
4400813 | 83 | Grupo de modelos:CARTEIRAS 2:4400773
4400814 | 83 | Grupo de modelos:CARTEIRAS 2:4400773
4400815 | 83 | Grupo de modelos:CARTEIRAS 2:4400773
4400816 | 83 | Grupo de modelos:CARTEIRAS 2:4400773
4400817 | 83 | Grupo de modelos:CARTEIRAS 2:4400773
4400818 | 83 | Grupo de modelos:CARTEIRAS 2:4400773
4400819 | 83 | Grupo de modelos:CARTEIRAS 2:4400773
4400820 | 83 | Grupo de modelos:CARTEIRAS 2:4400773
4400821 | 83 | Grupo de modelos:CARTEIRAS 2:4400773
4400822 | 83 | Grupo de modelos:CARTEIRAS 2:4400773
4400823 | 83 | Grupo de modelos:CARTEIRAS 2:4400773

# IfcFurnishingElement: Concrete_Bench_7009 (7)
Type - ElementType: Concrete_Bench_7009; Material: Concrete
Name (Banco Concreto:Concrete_Bench_7009:...) | In
4317291 | 118
4317430 | 118
4317686 | 118
4317687 | 118
4404828 | Nível 0.8
4405083 | 104
4409065 | Nível 0.8

# IfcFurnishingElement: Industrial_Stove_14527, Fogão Industrial:Industrial_Stove_14527:4298373
In: 90
Type - ElementType: Industrial_Stove_14527; Material: Metal - Chrome, Metal - Steel
Pset_ManufacturerTypeInformation - Manufacturer: Generic
Group: Grupo de modelos:Fogão:4298366

# IfcFurnishingElement: Mesa ADM 1.30x.60 (3)
Type - ElementType: Mesa ADM 1.30x.60; Material: Furniture_Watson_Seven_Leg, Furniture_Watson_Seven_Top
Pset_ManufacturerTypeInformation - Manufacturer: Watson Desking
Name (Watson_Seven_Rectangle:Mesa ADM 1.30x.60:...) | In
4348548 | 79
4348550 | 79
4349396 | 78

# IfcFurnishingElement: Mesa ADM 1.50x.60 (7)
Type - ElementType: Mesa ADM 1.50x.60; Material: Furniture_Watson_Seven_Leg, Furniture_Watson_Seven_Top
Pset_ManufacturerTypeInformation - Manufacturer: Watson Desking
Name (Watson_Seven_Rectangle:Mesa ADM 1.50x.60:...) | In
4339524 | 77
4340232 | 80
4340533 | 81
4340593 | 82
4342722 | 83
4345441 | 89
4349872 | 85

# IfcFurnishingElement: Mesa ADM 2.00x.70, Mesa_Escrivaninha:Mesa ADM 2.00x.70:4348316
In: 78
Type - ElementType: Mesa ADM 2.00x.70; Material: Furniture_Watson_Seven_Leg, Furniture_Watson_Seven_Top
Pset_ManufacturerTypeInformation - Manufacturer: Watson Desking

# IfcFurnishingElement: Mesa ADM 5.00x.60, Watson_Seven_Rectangle:Mesa ADM 5.00x.60:4352127
In: 94
Type - ElementType: Mesa ADM 5.00x.60; Material: Furniture_Watson_Seven_Leg, Furniture_Watson_Seven_Top
Pset_ManufacturerTypeInformation - Manufacturer: Watson Desking

# IfcFurnishingElement: Non-Upholstered (21)
In: 89
Type - ElementType: Non-Upholstered; Material: Furniture_Coalesse_Kart - Arm/Back/Seat (Poly), Furniture_Coalesse_Kart - Glide, Furniture_Coalesse_Kart - Flex Bar, Furniture_Coalesse_Kart - Frame
Pset_ManufacturerTypeInformation - Manufacturer: COALESSE
Name (COALESSE_KART_-_Stacking_Chair_8918:Non-Upholstered:...)
4345388
4345389
4345390
4345396
4345397
4345398
4345404
4345405
4345406
4345412
4345413
4345414
4345420
4345421
4345422
4345428
4345429
4345430
4345436
4345437
4345438

# IfcFurnishingElement: Quadro (7)
Type - ElementType: Quadro; Classification: C1030540 Chalkboards & Whiteboards (Uniformat); Material: Frame - Aluminum, Board Material - White Board, Plastic, Grey
Pset_ManufacturerTypeInformation - Manufacturer: Marsh Industries, Inc.
Name (Dry-Erase-Board_Electronic_Marsh:Quadro:...) | In
4339702 | 82
4340233 | 81
4340503 | 80
4340594 | 77
4342206 | Nível 1.2
4347902 | 90
4351990 | 86

# IfcFurnishingElement: Shelving_Unit_-_Fully_Parametric_12010 (8)
Type - ElementType: Shelving_Unit_-_Fully_Parametric_12010
Name (Shelving_Unit_-_Fully_Parametric_12010:Shelving_Unit_-_Fully_Parametric_12010:...) | In
4348551 | 79
4348552 | 79
4348553 | 79
4348838 | 79
4349580 | 78
4349581 | 78
4349582 | 78
4349583 | 78

# IfcFurnishingElement: Three Seater (6)
In: 101
Type - ElementType: Three Seater; Material: Seat Base, Seat Arms, Support Rail
Name (Cadeira Longarina:Three Seater:...)
4349657
4349722
4349752
4349794
4349795
4349796

# IfcMember: 6x5 cm (51)
In: COBERTURA BLOCO 01
Type - ElementType: 6x5 cm; PredefinedType: MEMBER
Material: .Madeira
Pset_MemberCommon - IsExternal: yes; LoadBearing: yes; Reference: 6x5 cm
Name (Rectangular Mullion:6x5 cm:...) | Span (m)
4444009 | 0.568644
4444010 | 1.08673
4444011 | 1.60481
4444012 | 2.1229
4444013 | 2.64098
4444014 | 2.66465
4444015 | 2.66465
4444016 | 2.66465
4444017 | 2.66465
4444018 | 2.66465
4444019 | 2.66465
4444020 | 2.66465
4444021 | 2.66465
4444022 | 2.66465
4444023 | 2.66465
4444024 | 2.66465
4444025 | 2.66465
4444026 | 2.66465
4444027 | 2.66465
4444028 | 2.66465
4444029 | 2.66465
4444030 | 2.66465
4444031 | 2.66465
4444032 | 2.66465
4444033 | 2.66465
4444034 | 2.66465
4444035 | 2.66465
4444036 | 2.66465
4444037 | 2.66465
4444038 | 2.66465
4444039 | 2.66465
4444040 | 2.66465
4444041 | 2.66465
4444042 | 2.61409
4444043 | 2.61409
4444044 | 2.61409
4444045 | 2.61409
4444046 | 2.61409
4444047 | 2.61409
4444048 | 2.61409
4444049 | 2.61409
4444050 | 2.61409
4444051 | 2.61409
4444052 | 2.61409
4444053 | 2.61409
4444054 | 2.61409
4444055 | 2.52797
4444056 | 2.02237
4444057 | 1.51678
4444058 | 1.01119
4444059 | 0.505594

# IfcMember: Caibro (189)
In: COBERTURA BLOCO 01
Type - ElementType: Caibro; PredefinedType: MEMBER
Material: .Madeira
Pset_MemberCommon - IsExternal: yes; LoadBearing: yes; Reference: Caibro
Name (Rectangular Mullion:Caibro:...) | Span (m)
4441218 | 4.52167
4441219 | 4.52167
4441220 | 4.52167
4441221 | 4.52167
4441222 | 4.52167
4441223 | 4.52167
4441224 | 4.52167
4441225 | 4.52167
4441226 | 4.52167
4441227 | 4.52167
4441228 | 4.52167
4441229 | 4.52167
4441230 | 4.52167
4441231 | 4.52167
4441232 | 4.52167
4441233 | 4.52167
4441234 | 4.52167
4441235 | 4.52167
4441236 | 4.52167
4441237 | 4.52167
4441238 | 4.52167
4441239 | 4.52167
4441240 | 4.52167
4441241 | 4.52167
4441242 | 4.52167
4441243 | 4.52167
4441244 | 4.52167
4441245 | 4.52167
4441246 | 4.52167
4441247 | 4.52167
4456004 | 4.50667
4456005 | 4.50667
4441183 | 4.52167
4441184 | 4.52167
4441185 | 4.52167
4441186 | 4.52167
4441187 | 4.52167
4441188 | 4.52167
4441189 | 4.52167
4441190 | 4.52167
4441191 | 4.52167
4441192 | 4.52167
4441193 | 4.52167
4441194 | 4.52167
4441195 | 4.52167
4441196 | 4.52167
4441197 | 4.52167
4441198 | 4.52167
4441199 | 4.52167
4441200 | 4.52167
4441201 | 4.52167
4441202 | 4.52167
4441203 | 4.52167
4441204 | 4.52167
4441205 | 4.52167
4441206 | 4.52167
4441207 | 4.52167
4441208 | 4.52167
4441209 | 4.52167
4441210 | 4.52167
4441211 | 4.52167
4441212 | 4.52167
4456002 | 4.50667
4456003 | 4.50667
4457707 | 2.97456
4457708 | 0.122753
4457812 | 0.811498
4457813 | 0.811498
4457814 | 0.811498
4457815 | 0.811498
4457816 | 0.775594
4457853 | 2.98956
4457854 | 2.98956
4457855 | 2.98956
4457856 | 2.98956
4457857 | 2.98956
4457858 | 2.98956
4457859 | 2.98956
4457860 | 2.98956
4457861 | 2.98956
4457862 | 2.88645
4457863 | 2.30401
4457864 | 1.72157
4457865 | 1.13912
4457866 | 0.556675
4457705 | 0.775594
4457706 | 2.97456
4457834 | 0.811498
4457835 | 0.811498
4457836 | 0.811498
4457837 | 0.811498
4457838 | 0.122753
4457839 | 0.556675
4457840 | 1.13912
4457841 | 1.72157
4457842 | 2.30401
4457843 | 2.88645
4457844 | 2.98956
4457845 | 2.98956
4457846 | 2.98956
4457847 | 2.98956
4457848 | 2.98956
4457849 | 2.98956
4457850 | 2.98956
4457851 | 2.98956
4457852 | 2.98956
4457703 | 0.800145
4457704 | 0.836048
4457817 | 0.836048
4457818 | 0.836048
4457819 | 0.836048
4457820 | 0.836048
4457821 | 0.836048
4457822 | 0.836048
4457823 | 0.836048
4457824 | 0.800145
4457825 | 0.574296
4457826 | 1.17436
4457827 | 1.77443
4457828 | 2.37449
4457829 | 2.97456
4457830 | 2.37449
4457831 | 1.77443
4457832 | 1.17436
4457833 | 0.574296
4465949 | 4.43311
4465950 | 4.43311
4466078 | 4.44811
4466079 | 4.44811
4466080 | 4.44811
4466081 | 4.44811
4466082 | 4.44811
4466083 | 4.44811
4466084 | 4.44811
4466085 | 4.44811
4466086 | 4.44811
4466087 | 4.44811
4466088 | 4.44811
4466089 | 4.44811
4466090 | 4.44811
4466091 | 4.44811
4466092 | 4.44811
4466093 | 4.44811
4466094 | 4.44811
4466095 | 4.44811
4466096 | 4.44811
4466097 | 4.44811
4466098 | 4.44811
4466099 | 4.44811
4466100 | 4.44811
4466101 | 4.44811
4466102 | 4.44811
4466103 | 4.44811
4466104 | 4.44811
4466105 | 4.44811
4466106 | 4.44811
4465951 | 2.91271
4465952 | 4.43311
4465953 | 4.43311
4465954 | 2.91271
4466107 | 4.44811
4466108 | 4.44811
4466109 | 4.44811
4466110 | 4.44811
4466111 | 4.44811
4466112 | 4.44811
4466113 | 4.44811
4466114 | 4.44811
4466115 | 4.44811
4466116 | 4.44811
4466117 | 4.44811
4466118 | 4.44811
4466119 | 4.44811
4466120 | 4.44811
4466121 | 4.44811
4466122 | 4.44811
4466123 | 4.44811
4466124 | 1.5354
4466125 | 1.5354
4466126 | 1.5354
4466127 | 4.44811
4466128 | 4.44811
4466129 | 4.44811
4466130 | 4.44811
4466131 | 4.44811
4466132 | 4.44811
4466133 | 4.44811
4466134 | 4.44811
4466135 | 4.44811

# IfcMember: Ripa (93)
In: COBERTURA BLOCO 01
Type - ElementType: Ripa; PredefinedType: MEMBER
Material: .Madeira
Pset_MemberCommon - IsExternal: yes; LoadBearing: yes; Reference: Ripa
Name (Rectangular Mullion:Ripa:...) | Span (m)
4441272 | 18.4962
4441321 | 18.4962
4441322 | 18.4962
4441323 | 18.4962
4441324 | 18.4962
4441325 | 18.4962
4441326 | 18.4962
4441327 | 18.4962
4441328 | 18.4962
4441329 | 18.4962
4441330 | 18.4962
4441331 | 18.4962
4441273 | 18.4962
4441332 | 18.4962
4441333 | 18.4962
4441334 | 18.4962
4441335 | 18.4962
4441336 | 18.4962
4441337 | 18.4962
4441338 | 18.4962
4441339 | 18.4962
4441340 | 18.4962
4441341 | 18.4962
4441342 | 18.4962
4444097 | 17.42
4444138 | 15.2042
4444139 | 15.5736
4444140 | 15.943
4444141 | 16.3124
4444142 | 16.6818
4444143 | 17.0512
4444098 | 9.5
4444144 | 7.27708
4444145 | 7.63933
4444146 | 8.00157
4444147 | 8.36382
4444148 | 8.72606
4444149 | 9.08831
4456469 | 5.22506
4456470 | 4.47862
4456471 | 3.73218
4456472 | 2.98575
4456473 | 2.23931
4456474 | 1.49287
4456475 | 0.746437
4456401 | 5.49007
4456483 | 8.10866
4456484 | 7.74151
4456485 | 7.37435
4456486 | 7.0072
4456487 | 6.64004
4456488 | 6.27289
4456489 | 5.90573
4456400 | 5.49007
4456476 | 8.10866
4456477 | 7.74151
4456478 | 7.37435
4456479 | 7.0072
4456480 | 6.64004
4456481 | 6.27289
4456482 | 5.90573
4462937 | 17.57
4462997 | 10
4462998 | 5.42
4462999 | 10
4463000 | 5.42
4463001 | 10
4463002 | 5.42
4463003 | 10
4463004 | 5.42
4463005 | 10
4463006 | 5.42
4463007 | 10
4463008 | 5.42
4463009 | 10
4463010 | 5.42
4463011 | 10
4463012 | 5.42
4463013 | 17.57
4463014 | 17.57
4463015 | 17.57
4462936 | 17.57
4462986 | 17.57
4462987 | 17.57
4462988 | 17.57
4462989 | 17.57
4462990 | 17.57
4462991 | 17.57
4462992 | 17.57
4462993 | 17.57
4462994 | 17.57
4462995 | 17.57
4462996 | 17.57

# IfcMember: Terça (26)
In: COBERTURA BLOCO 01
Type - ElementType: Terça; PredefinedType: MEMBER
Material: .Madeira
Pset_MemberCommon - IsExternal: yes; LoadBearing: yes; Reference: Terça
Name (Rectangular Mullion:Terça:...) | Span (m)
4441361 | 18.4962
4441371 | 18.4962
4456040 | 18.4962
4441363 | 18.4962
4441372 | 18.4962
4456041 | 18.4962
4444185 | 14.8348
4444186 | 17.42
4444200 | 16.872
4444187 | 6.91483
4444188 | 9.5
4444201 | 8.95204
4456317 | 5.49007
4456336 | 6.56464
4456319 | 5.49007
4456337 | 6.56464
4456315 | 5.97149
4456335 | 2.03271
4463375 | 17.57
4463398 | 17.57
4463399 | 17.57
4463377 | 2.15
4463379 | 17.57
4463400 | 10
4463401 | 5.42
4463402 | 17.57

# IfcRailing: Guarda-corpo:Peitoril 1.10 m (2)
In: Nível 0
Material: .Alumínio, .Aço escovado
Pset_RailingCommon - IsExternal: no; Reference: Peitoril 1.10 m; Height: 1.2192 m
Name (Guarda-corpo:Peitoril 1.10 m:...)
4353626
4353630

# IfcRamp: Rampa:8.33% sólida:885167, Rampa:8.33% sólida:4163916
In: Nível 1.2
Pset_RampCommon - IsExternal: no; Reference: 8.33% sólida

# IfcRamp: Rampa:8.33%:710952, Rampa:8.33%:4353546
In: Nível 0
Pset_RampCommon - IsExternal: no; Reference: 8.33%

# IfcRampFlight: Rampa:8.33% sólida:885167, Rampa:8.33% sólida:4163916:1
In: Nível 1.2
Material: .Cimentício branco
Pset_RampFlightCommon - Reference: 8.33% sólida

# IfcRampFlight: Rampa:8.33%:710952, Rampa:8.33%:4353546:1
In: Nível 0
Material: .Concreto
Pset_RampFlightCommon - Reference: 8.33%

# IfcRoof: Telhado básico:Algeroz:497146, Telhado básico:Algeroz:4467643
In: COBERTURA BLOCO 01
Material: .Concreto
Pset_RoofCommon - IsExternal: yes; Reference: Algeroz; TotalArea: 2.87887 m2; ProjectedArea: 2.79291 m2

# IfcRoof: Telhado básico:Telha Canal:1748915 (6)
In: COBERTURA BLOCO 01
Material: .Telha canal
Pset_RoofCommon - IsExternal: yes; Reference: Telha Canal
Name (Telhado básico:Telha Canal:...) | TotalArea (m2) | ProjectedArea (m2)
4176323 | 260.916 | 253.125
4355290 | 82.0811 | 79.6304
4440693 | 167.637 | 162.632
4441713 | 152.86 | 148.296
4443870 | 65.5694 | 64.844
4456380 | 52.7453 | 51.1704

# IfcRoof: Vidraça inclinada:.Caibros Metálicos, Vidraça inclinada:.Caibros Metálicos:4443842
In: COBERTURA BLOCO 01
Pset_RoofCommon - IsExternal: yes; Reference: .Caibros Metálicos; ProjectedArea: 64.103 m2

# IfcRoof: Vidraça inclinada:M - Caibros (3)
In: COBERTURA BLOCO 01
Pset_RoofCommon - IsExternal: yes; Reference: M - Caibros
Name (Vidraça inclinada:M - Caibros:...) | ProjectedArea (m2)
4440670 | 162.632
4456359 | 49.4704
4465912 | 145.853

# IfcRoof: Vidraça inclinada:M - Ripas (4)
In: COBERTURA BLOCO 01
Pset_RoofCommon - IsExternal: yes; Reference: M - Ripas
Name (Vidraça inclinada:M - Ripas:...) | ProjectedArea (m2)
4440646 | 162.632
4443723 | 64.103
4456295 | 51.1704
4462900 | 151.924

# IfcRoof: Vidraça inclinada:M - Terças (4)
In: COBERTURA BLOCO 01
Pset_RoofCommon - IsExternal: yes; Reference: M - Terças
Name (Vidraça inclinada:M - Terças:...) | ProjectedArea (m2)
4177770 | 162.632
4178037 | 64.103
4348153 | 51.1704
4463338 | 151.924

# IfcSlab: Piso:.Laje .15 (4)
In: Nível 1.2
PredefinedType: FLOOR; Material: Concreto, Moldado no local - Cinza 0.125 m, Acabamento Verde 0.025 m
Pset_SlabCommon - LoadBearing: no; IsExternal: no; PitchAngle: 0 deg; Reference: .Laje .15; ThermalTransmittance: 8.368 kg/K/s3
Name (Piso:.Laje .15:...)
4361749
4363900
4363931
4363963

# IfcSlab: Piso:.Piso Externo-Bloco Intertravado (2)
PredefinedType: FLOOR; Material: .Piso intertravado 0.01 m, .Cimentado 0.03 m, .Lastro de Concreto 0.05 m, .Aterro Compactado 0.11 m
Pset_SlabCommon - LoadBearing: no; IsExternal: no; PitchAngle: 0 deg; Reference: .Piso Externo-Bloco Intertravado; ThermalTransmittance: 2.65845 kg/K/s3
Name (Piso:.Piso Externo-Bloco Intertravado:...) | In
4107813 | Nível 0.8
4136695 | Nível 1.2

# IfcSlab: Piso:.Piso_Área Molhada_40x40 (10)
PredefinedType: FLOOR; Material: .CERÂMICA 40x40 BRANCA 0.01 m, .Cimentado 0.03 m, .Lastro de Concreto 0.12 m
Pset_SlabCommon - LoadBearing: no; IsExternal: no; Reference: .Piso_Área Molhada_40x40; ThermalTransmittance: 8.12638 kg/K/s3
Name (Piso:.Piso_Área Molhada_40x40:...) | In | PitchAngle (deg)
4087931 | Nível 1.2 | 0
4088571 | Nível 1.2 | 0
4089705 | Nível 1.2
4089705:2 | Nível 1.2
4308285 | Nível 1.2
4308285:2 | Nível 1.2
4332598 | Nível 0.8 | 0
4396921 | Nível 1.2 | 0
4454283 | Nível 1.2 | 0
4454327 | Nível 1.2 | 0

# IfcSlab: Piso:Grama (5)
In: Nível 1.2
PredefinedType: FLOOR; Material: .Grama 1 m
Pset_SlabCommon - LoadBearing: no; IsExternal: no; PitchAngle: 0 deg; Reference: Grama
Name (Piso:Grama:...)
4109340
4311397
4311597
4311657
4318032

# IfcSlab: Piso:Granilite (11)
PredefinedType: FLOOR; Material: .Granilite areia com junta de dilatação 1x1m 0.1 m
Pset_SlabCommon - LoadBearing: no; IsExternal: no; Reference: Granilite
Name (Piso:Granilite:...) | In | PitchAngle (deg)
4092136 | Nível 1.2 | 0
4093351 | Nível 1.2 | 0
4104769 | Nível 1.2 | 0
4131779 | Nível 1.2 | 0
4131807 | Nível 1.2
4131934 | Nível 1.2
4131934:2 | Nível 1.2
4131991 | Nível 1.2 | 0
4132045 | Nível 1.2 | 0
4136663 | Nível 1.2 | 0
4332566 | Nível 0.8 | 0

# IfcSlab: Piso:Piso Externo_Cimentado (2)
In: Nível 1.2
PredefinedType: FLOOR; Material: .Cimentado áspero com junta de dilatação 0.06 m, .Lastro de Concreto 1.05 m, .Aterro Compactado 0.09 m
Pset_SlabCommon - LoadBearing: no; IsExternal: no; PitchAngle: 0 deg; Reference: Piso Externo_Cimentado; ThermalTransmittance: 0.785866 kg/K/s3
Name (Piso:Piso Externo_Cimentado:...)
4215060
4454034

# IfcSlab: Piso:Piso Palco, Piso:Piso Palco:4163544
In: Nível 1.2
PredefinedType: FLOOR; Material: .Granilite areia com junta de dilatação 1x1m 0.53 m
Pset_SlabCommon - LoadBearing: no; IsExternal: no; PitchAngle: 0 deg; Reference: Piso Palco

# IfcStair: Escada moldada no local:Escada monolítica:2833672 (4)
Pset_StairCommon - IsExternal: no; Reference: Escada monolítica
Name (Escada moldada no local:Escada:...) | In | NumberOfRiser | NumberOfTreads | RiserHeight (m) | TreadLength (m)
3973089 | Nível 1.2 | 3 | 2 | 0.0666667 | 0.39
4106907 | Nível 0.8 | 2 | 1 | 0.175 | 0.28
4107484 | Nível 0.8 | 2 | 1 | 0.175 | 0.28
4109184 | Nível 1.2 | 2 | 1 | 0.1 | 0.43

# IfcStairFlight: Escada moldada no local:Escada monolítica:2833672 (4)
Material: .Pintura branca, .Concreto
Pset_StairFlightCommon - Reference: 25 mm Tread 25 mm Riser; NosingLength: 0 m
Name (Escada moldada no local:Escada:...) | In | NumberOfRiser = Pset_StairFlightCommon, NumberOfRiser | NumberOfTreads = Pset_StairFlightCommon, NumberOfTreads | RiserHeight (m) | TreadLength (m) | Pset_StairFlightCommon, RiserHeight (m) | Pset_StairFlightCommon, TreadLength (m) = TreadLengthAtOffset (m) | WalkingLineOffset (m) | WaistThickness (m)
3973089 Run 1 | Nível 1.2 | 3 | 2 | 0.218723 | 1.27953 | 0.0666667 | 0.39 | 3.5475 | 7.095
4106907 Run 1 | Nível 0.8 | 2 | 1 | 0.574147 | 0.918635 | 0.175 | 0.28 | 2.81 | 5.62
4107484 Run 1 | Nível 0.8 | 2 | 1 | 0.574147 | 0.918635 | 0.175 | 0.28 | 7.40803 | 14.8161
4109184 Run 1 | Nível 1.2 | 2 | 1 | 0.328084 | 1.41076 | 0.1 | 0.43 | 0.955 | 1.91

# IfcWall: Parede básica:ECeramica branca 10x10cm (3)
Type - PredefinedType: STANDARD; Material: .CERÂMICA 10x10 BRANCA 0.0035 m, Argamassa Colante 0.02 m, 4 0.0015 m, 3 0.005 m
Pset_WallCommon - LoadBearing: no; ExtendToStructure: yes; IsExternal: yes; Reference: ECeramica branca 10x10cm; ThermalTransmittance: 45.378 kg/K/s3
Name (Parede básica:ECeramica branca 10x10cm:...) | In
4242664 | Nível 1.2
4247523 | Nível 1.2
4328296 | Nível 0.8

# IfcWall: Parede básica:ENucleo parede 15cm (8)
In: Nível 1.2
Type - PredefinedType: STANDARD; Material: ALVENARIA 0.09 m
Pset_WallCommon - Reference: ENucleo parede 15cm; LoadBearing: no; ExtendToStructure: no; IsExternal: no
Name (Parede básica:ENucleo parede 15cm:...)
4217030
4217032
4217131
4217132
4217133
4217134
4217145
4353282

# IfcWallStandardCase: Parede básica:10cm - Canteiros (7)
Type - PredefinedType: STANDARD; Material: .Pintura branca 0.005 m, .Alvenaria 0.09 m, .Pintura branca 0.005 m
Pset_WallCommon - LoadBearing: no; IsExternal: yes; Reference: 10cm - Canteiros
Name (Parede básica:10cm - Canteiros:...) | In | ExtendToStructure
4310674 | Nível 1.2 | yes
4310943 | Nível 1.2 | yes
4310995 | Nível 1.2 | yes
4311105 | Nível 0.8 | no
4311247 | Nível 0.8 | no
4314089 | Nível 1.2 | yes
4317863 | Nível 1.2 | yes

# IfcWallStandardCase: Parede básica:ECeramica Verde 10x10cm (4)
In: Nível 1.2
Type - PredefinedType: STANDARD; Material: .CERÂMICA 10x10 VERDE 0.0035 m, Argamassa Colante 0.02 m, 4 0.0015 m, 3 0.005 m
Pset_WallCommon - LoadBearing: no; ExtendToStructure: no; IsExternal: yes; Reference: ECeramica Verde 10x10cm; ThermalTransmittance: 45.378 kg/K/s3
Name (Parede básica:ECeramica Verde 10x10cm:...)
4394828
4395285
4396124
4396465

# IfcWallStandardCase: Parede básica:ECeramica branca 10x10cm (115)
Type - PredefinedType: STANDARD; Material: .CERÂMICA 10x10 BRANCA 0.0035 m, Argamassa Colante 0.02 m, 4 0.0015 m, 3 0.005 m
Pset_WallCommon - LoadBearing: no; IsExternal: yes; Reference: ECeramica branca 10x10cm; ThermalTransmittance: 45.378 kg/K/s3
Name (Parede básica:ECeramica branca 10x10cm:...) | In | ExtendToStructure
4236521 | Nível 1.2 | no
4237199 | Nível 1.2 | no
4237308 | Nível 1.2 | no
4237404 | Nível 1.2 | no
4237657 | Nível 1.2 | no
4237843 | Nível 1.2 | no
4237921 | Nível 1.2 | no
4238217 | Nível 1.2 | no
4238219 | Nível 1.2 | no
4238339 | Nível 1.2 | no
4238506 | Nível 1.2 | no
4238633 | Nível 1.2 | no
4239480 | Nível 1.2 | no
4239632 | Nível 1.2 | no
4239775 | Nível 1.2 | no
4240159 | Nível 1.2 | no
4240310 | Nível 1.2 | no
4240460 | Nível 1.2 | no
4240562 | Nível 1.2 | no
4241264 | Nível 1.2 | no
4241403 | Nível 1.2 | no
4241494 | Nível 1.2 | no
4241873 | Nível 1.2 | no
4242980 | Nível 1.2 | no
4243198 | Nível 1.2 | no
4243371 | Nível 1.2 | no
4243550 | Nível 1.2 | no
4243850 | Nível 1.2 | no
4244175 | Nível 1.2 | no
4244508 | Nível 1.2 | no
4244621 | Nível 1.2 | no
4244740 | Nível 1.2 | no
4244896 | Nível 1.2 | no
4245117 | Nível 1.2 | no
4245216 | Nível 1.2 | no
4245627 | Nível 1.2 | no
4245720 | Nível 1.2 | no
4245853 | Nível 1.2 | no
4246030 | Nível 1.2 | no
4246175 | Nível 1.2 | no
4246279 | Nível 1.2 | no
4246475 | Nível 1.2 | no
4246608 | Nível 1.2 | no
4247346 | Nível 1.2 | no
4247667 | Nível 1.2 | no
4247800 | Nível 1.2 | no
4247966 | Nível 1.2 | no
4248085 | Nível 1.2 | yes
4248180 | Nível 1.2 | no
4248304 | Nível 1.2 | no
4248455 | Nível 1.2 | no
4248566 | Nível 1.2 | no
4248717 | Nível 1.2 | yes
4248851 | Nível 1.2 | no
4249022 | Nível 1.2 | no
4249146 | Nível 1.2 | no
4249270 | Nível 1.2 | no
4249430 | Nível 1.2 | no
4249607 | Nível 1.2 | no
4249750 | Nível 1.2 | no
4249884 | Nível 1.2 | no
4250226 | Nível 1.2 | no
4250452 | Nível 1.2 | no
4250598 | Nível 1.2 | no
4250705 | Nível 1.2 | no
4250842 | Nível 1.2 | no
4250969 | Nível 1.2 | no
4251094 | Nível 1.2 | no
4251238 | Nível 1.2 | no
4251430 | Nível 1.2 | no
4251592 | Nível 1.2 | no
4251751 | Nível 1.2 | no
4252024 | Nível 1.2 | no
4252417 | Nível 1.2 | no
4257569 | Nível 1.2 | yes
4257844 | Nível 1.2 | no
4258099 | Nível 1.2 | no
4258884 | Nível 1.2 | no
4259144 | Nível 1.2 | no
4263152 | Nível 1.2 | no
4276986 | Nível 1.2 | no
4276987 | Nível 1.2 | no
4276988 | Nível 1.2 | no
4276992 | Nível 1.2 | no
4276993 | Nível 1.2 | no
4276994 | Nível 1.2 | no
4277019 | Nível 1.2 | no
4277020 | Nível 1.2 | no
4277021 | Nível 1.2 | no
4277025 | Nível 1.2 | no
4277026 | Nível 1.2 | no
4277027 | Nível 1.2 | no
4303233 | Nível 1.2 | no
4303516 | Nível 1.2 | yes
4304154 | Nível 1.2 | no
4306332 | Nível 1.2 | no
4306578 | Nível 1.2 | no
4307653 | Nível 1.2 | yes
4320918 | Nível 0.8 | no
4320944 | Nível 1.2 | no
4327418 | Nível 1.2 | no
4328858 | Nível 0.8 | no
4331388 | Nível 1.2 | no
4335931 | Nível 1.2 | no
4335953 | Nível 1.2 | no
4394827 | Nível 1.2 | no
4394829 | Nível 1.2 | no
4395284 | Nível 1.2 | no
4395286 | Nível 1.2 | no
4396123 | Nível 1.2 | no
4396125 | Nível 1.2 | no
4396464 | Nível 1.2 | no
4396466 | Nível 1.2 | no
4459859 | Nível 1.2 | no
4459863 | Nível 1.2 | no

# IfcWallStandardCase: Parede básica:EGenérica (2)
In: Nível 0
Type - PredefinedType: STANDARD; Material: Acabamento Branco 0.0035 m, Massa corrida 0.02 m, 4 0.0015 m, 3 0.005 m
Pset_WallCommon - LoadBearing: no; ExtendToStructure: no; IsExternal: yes; Reference: EGenérica
Name (Parede básica:EGenérica:...)
4038375
4158839

# IfcWallStandardCase: Parede básica:ENucleo parede 15cm (85)
Type - PredefinedType: STANDARD; Material: ALVENARIA 0.09 m
Pset_WallCommon - Reference: ENucleo parede 15cm; LoadBearing: no; IsExternal: no
Name (Parede básica:ENucleo parede 15cm:...) | In | ExtendToStructure
3908423 | Nível 1.2 | no
3908839 | Nível 1.2 | no
3909387 | Nível 1.2 | no
3915926 | Nível 1.2 | no
3916269 | Nível 1.2 | yes
3916506 | Nível 1.2 | no
3921342 | Nível 1.2 | yes
3921636 | Nível 1.2 | no
3921808 | Nível 1.2 | yes
3931004 | Nível 1.2 | no
3931297 | Nível 1.2 | no
3931596 | Nível 1.2 | no
3933533 | Nível 1.2 | no
3933799 | Nível 1.2 | no
3934225 | Nível 1.2 | no
3934463 | Nível 1.2 | no
3935641 | Nível 1.2 | no
3935950 | Nível 1.2 | no
3936456 | Nível 1.2 | no
3937264 | Nível 1.2 | no
3937453 | Nível 1.2 | yes
3937802 | Nível 1.2 | yes
3938613 | Nível 1.2 | no
3940691 | Nível 1.2 | no
3944195 | Nível 1.2 | no
3945065 | Nível 1.2 | no
3945263 | Nível 1.2 | no
3945415 | Nível 1.2 | no
3947895 | Nível 1.2 | no
3949435 | Nível 1.2 | no
3950748 | Nível 1.2 | no
3951487 | Nível 1.2 | no
3954222 | Nível 1.2 | no
3954890 | Nível 1.2 | no
3954984 | Nível 1.2 | no
3958748 | Nível 1.2 | no
3961231 | Nível 1.2 | no
3977980 | Nível 1.2 | no
3983598 | Nível 1.2 | no
3983984 | Nível 1.2 | no
3985873 | Nível 1.2 | no
3986459 | Nível 1.2 | no
4007714 | Nível 1.2 | no
4014039 | Nível 0.8 | no
4041096 | Nível 1.2 | no
4086756 | Nível 1.2 | yes
4147431 | Nível 1.2 | no
4153032 | Nível 1.2 | no
4195919 | Nível 1.2 | yes
4196816 | Nível 1.2 | no
4210516 | Nível 1.2 | no
4217005 | Nível 1.2 | no
4217007 | Nível 1.2 | no
4217009 | Nível 1.2 | no
4217033 | Nível 1.2 | no
4217034 | Nível 1.2 | no
4217135 | Nível 1.2 | no
4217136 | Nível 1.2 | no
4217137 | Nível 1.2 | no
4217138 | Nível 1.2 | no
4217139 | Nível 1.2 | no
4217148 | Nível 1.2 | no
4236838 | Nível 1.2 | no
4238218 | Nível 1.2 | no
4239107 | Nível 1.2 | no
4239248 | Nível 1.2 | no
4302856 | Nível 1.2 | no
4303099 | Nível 1.2 | yes
4306465 | Nível 1.2 | no
4307654 | Nível 1.2 | yes
4327886 | Nível 0.8 | yes
4328502 | Nível 0.8 | yes
4331103 | Nível 0.8 | no
4332707 | Nível 1.2 | no
4332708 | Nível 1.2 | no
4332711 | Nível 1.2 | no
4353252 | Nível 1.2 | yes
4353253 | Nível 1.2 | yes
4354181 | Nível 1.2 | no
4394970 | Nível 1.2 | no
4395426 | Nível 1.2 | no
4464722 | Nível 1.2 | no
4465492 | Nível 1.2 | no
4466685 | Nível 1.2 | no
4467171 | Nível 1.2 | no

# IfcWallStandardCase: Parede básica:EPintura Branca (62)
Type - PredefinedType: STANDARD; Material: Acabamento Branco 0.0035 m, Massa corrida 0.02 m, 4 0.0015 m, 3 0.005 m
Pset_WallCommon - LoadBearing: no; IsExternal: yes; Reference: EPintura Branca
Name (Parede básica:EPintura Branca:...) | In | ExtendToStructure
4240836 | Nível 1.2 | no
4240926 | Nível 1.2 | no
4240982 | Nível 1.2 | no
4241104 | Nível 1.2 | no
4242665 | Nível 1.2 | yes
4242981 | Nível 1.2 | no
4243199 | Nível 1.2 | no
4243372 | Nível 1.2 | no
4243551 | Nível 1.2 | no
4243851 | Nível 1.2 | no
4244176 | Nível 1.2 | no
4244509 | Nível 1.2 | no
4244622 | Nível 1.2 | no
4244741 | Nível 1.2 | no
4244897 | Nível 1.2 | no
4245118 | Nível 1.2 | no
4245217 | Nível 1.2 | no
4245628 | Nível 1.2 | no
4245721 | Nível 1.2 | no
4245854 | Nível 1.2 | no
4246031 | Nível 1.2 | no
4246176 | Nível 1.2 | no
4246280 | Nível 1.2 | no
4246476 | Nível 1.2 | no
4246609 | Nível 1.2 | no
4247347 | Nível 1.2 | no
4247524 | Nível 1.2 | yes
4247668 | Nível 1.2 | no
4247801 | Nível 1.2 | no
4247967 | Nível 1.2 | no
4248086 | Nível 1.2 | yes
4248181 | Nível 1.2 | no
4248305 | Nível 1.2 | no
4248456 | Nível 1.2 | no
4248567 | Nível 1.2 | no
4248718 | Nível 1.2 | yes
4248852 | Nível 1.2 | no
4249023 | Nível 1.2 | no
4249147 | Nível 1.2 | no
4249271 | Nível 1.2 | no
4249431 | Nível 1.2 | no
4249608 | Nível 1.2 | no
4249751 | Nível 1.2 | no
4249885 | Nível 1.2 | no
4250227 | Nível 1.2 | no
4250453 | Nível 1.2 | no
4250599 | Nível 1.2 | no
4250706 | Nível 1.2 | no
4250843 | Nível 1.2 | no
4250970 | Nível 1.2 | no
4251095 | Nível 1.2 | no
4251239 | Nível 1.2 | no
4251431 | Nível 1.2 | no
4320919 | Nível 0.8 | no
4320945 | Nível 1.2 | no
4328297 | Nível 0.8 | yes
4328859 | Nível 0.8 | no
4335932 | Nível 1.2 | no
4335954 | Nível 1.2 | no
4366648 | Nível 1.2 | no
4459860 | Nível 1.2 | no
4459864 | Nível 1.2 | no

# IfcWallStandardCase: Parede básica:EPintura amarela (36)
Type - PredefinedType: STANDARD; Material: Acabamento amarelo 0.0035 m, Massa corrida 0.02 m, 4 0.0015 m, 3 0.005 m
Pset_WallCommon - LoadBearing: no; IsExternal: yes; Reference: EPintura amarela
Name (Parede básica:EPintura amarela:...) | In | ExtendToStructure
4252983 | Nível 1.2 | no
4253478 | Nível 1.2 | no
4253714 | Nível 1.2 | yes
4253960 | Nível 1.2 | no
4254164 | Nível 1.2 | no
4254351 | Nível 1.2 | no
4256354 | Nível 1.2 | no
4256520 | Nível 1.2 | no
4256739 | Nível 1.2 | no
4257121 | Nível 1.2 | no
4257271 | Nível 1.2 | no
4258705 | Nível 1.2 | no
4259569 | Nível 1.2 | no
4259977 | Nível 1.2 | no
4260143 | Nível 1.2 | no
4260437 | Nível 1.2 | no
4260706 | Nível 1.2 | no
4261110 | Nível 1.2 | no
4261255 | Nível 1.2 | no
4261473 | Nível 1.2 | no
4261610 | Nível 1.2 | no
4262092 | Nível 1.2 | yes
4262655 | Nível 1.2 | no
4263487 | Nível 1.2 | no
4263802 | Nível 1.2 | yes
4302543 | Nível 1.2 | no
4302653 | Nível 1.2 | yes
4307655 | Nível 1.2 | yes
4309777 | Nível 1.2 | no
4319619 | Nível 1.2 | no
4329028 | Nível 0.8 | yes
4332045 | Nível 0.8 | yes
4354403 | Nível 1.2 | yes
4395791 | Nível 1.2 | no
4464387 | Nível 1.2 | no
4465264 | Nível 1.2 | no

# IfcWallStandardCase: Parede básica:INTERNA .15 - REVESTIMENTO BRANCO (21)
In: Nível 1.2
Type - PredefinedType: STANDARD; Material: .CERÂMICA 10x10 BRANCA 0.005 m, Argamassa Cola 0.0175 m, Tijolo, comum, marrom 0.105 m, Argamassa Cola 0.0175 m, .CERÂMICA 10x10 BRANCA 0.005 m
Pset_WallCommon - LoadBearing: no; ExtendToStructure: no; IsExternal: yes; Reference: INTERNA .15 - REVESTIMENTO BRANCO; ThermalTransmittance: 4.23301 kg/K/s3
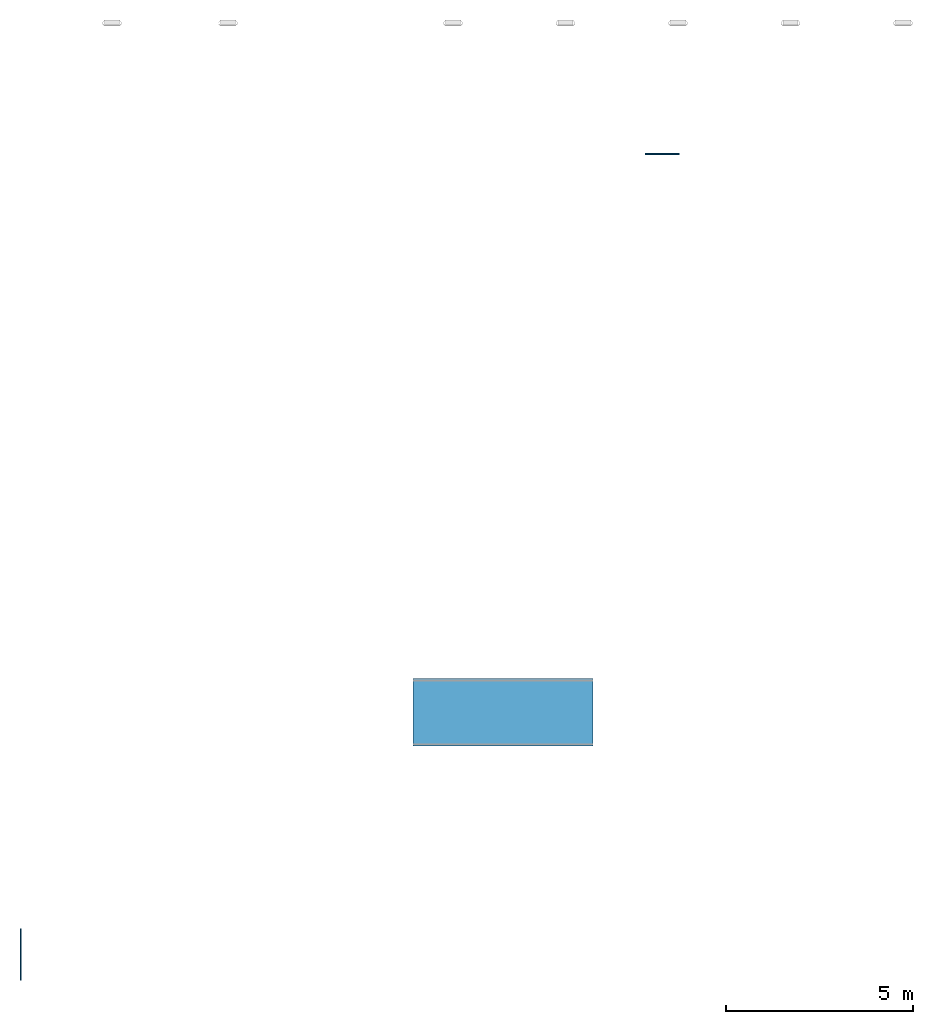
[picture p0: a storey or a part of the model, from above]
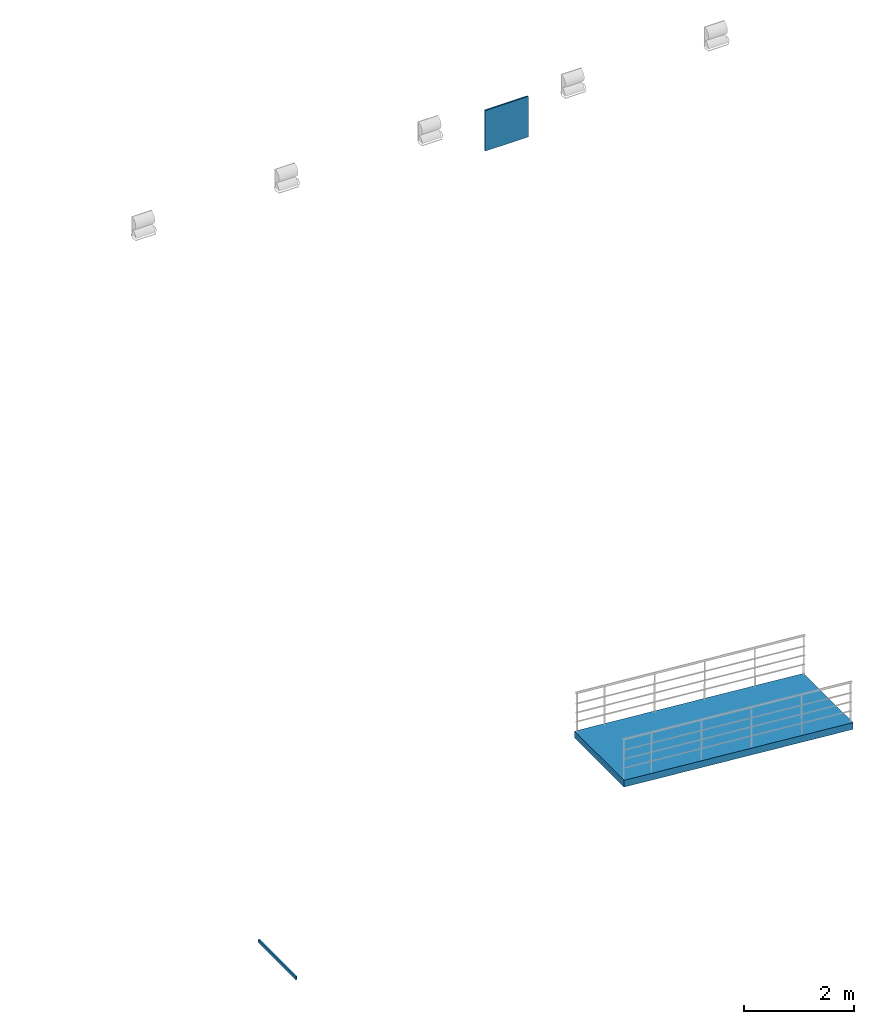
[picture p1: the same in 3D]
Properties of the parts of a building model (IFC2X3), part 2 of 2

# IfcWallStandardCase: Parede básica:INTERNA .15 - REVESTIMENTO BRANCO (21)
Name (Parede básica:INTERNA .15 - REVESTIMENTO BRANCO:...) | Group
4345384 | Grupo de modelos:Bancada Informática:4345391
4345385 | Grupo de modelos:Bancada Informática:4345391
4345386 | Grupo de modelos:Bancada Informática:4345391
4345392 | Grupo de modelos:Bancada Informática:4345399
4345393 | Grupo de modelos:Bancada Informática:4345399
4345394 | Grupo de modelos:Bancada Informática:4345399
4345400 | Grupo de modelos:Bancada Informática:4345407
4345401 | Grupo de modelos:Bancada Informática:4345407
4345402 | Grupo de modelos:Bancada Informática:4345407
4345408 | Grupo de modelos:Bancada Informática:4345415
4345409 | Grupo de modelos:Bancada Informática:4345415
4345410 | Grupo de modelos:Bancada Informática:4345415
4345416 | Grupo de modelos:Bancada Informática:4345423
4345417 | Grupo de modelos:Bancada Informática:4345423
4345418 | Grupo de modelos:Bancada Informática:4345423
4345424 | Grupo de modelos:Bancada Informática:4345431
4345425 | Grupo de modelos:Bancada Informática:4345431
4345426 | Grupo de modelos:Bancada Informática:4345431
4345432 | Grupo de modelos:Bancada Informática:4345439
4345433 | Grupo de modelos:Bancada Informática:4345439
4345434 | Grupo de modelos:Bancada Informática:4345439

# IfcWindow: 100 x 50 (2)
In: Nível 1.2
Type - ParameterTakesPrecedence: no; Sizeable: no; Material: VIDRO COMUM LISO VERDE, ALUMÍNIO COM PINTURA ELETROSTÁTICA BRANCA
OverallHeight: 0.57 m; OverallWidth: 1.07 m
Pset_WindowCommon - IsExternal: no; Reference: 100 x 50
Name (Janela 100x50:100 x 50:...)
4445989
4446234

# IfcWindow: 100 x 51., Janela 100x50:100 x 51.:4332751
In: Nível 1.2
Type - ParameterTakesPrecedence: no; Sizeable: no; Material: VIDRO COMUM LISO VERDE, ALUMÍNIO COM PINTURA ELETROSTÁTICA BRANCA
OverallHeight: 0.57 m; OverallWidth: 1.07 m
Pset_WindowCommon - IsExternal: no; Reference: 100 x 51.

# IfcWindow: 130 x 200cm 2 (29)
Type - ParameterTakesPrecedence: no; Sizeable: no; Material: Pintura Azul
OverallHeight: 2 m; OverallWidth: 1.3 m
Pset_WindowCommon - IsExternal: no; Reference: 130 x 200cm 2
Name (Janela levantamento:130 x 200cm 2:...) | In
3975686 | Nível 1.2
3975784 | Nível 1.2
3976007 | Nível 1.2
3976712 | Nível 1.2
3978422 | Nível 1.2
3978548 | Nível 1.2
3979016 | Nível 1.2
3979068 | Nível 1.2
3979204 | Nível 1.2
3979312 | Nível 1.2
3979520 | Nível 1.2
3979610 | Nível 1.2
3980093 | Nível 1.2
3980300 | Nível 1.2
3980602 | Nível 1.2
3980712 | Nível 1.2
3980822 | Nível 1.2
3980878 | Nível 1.2
3980966 | Nível 1.2
3981048 | Nível 1.2
3981120 | Nível 1.2
3981258 | Nível 1.2
3981332 | Nível 1.2
4215515 | Nível 1.2
4329779 | Nível 0.8
4329961 | Nível 0.8
4330809 | Nível 0.8
4333458 | Nível 1.2
4333459 | Nível 1.2

# IfcWindow: 150 x 50 (6)
In: Nível 1.2
Type - ParameterTakesPrecedence: no; Sizeable: no; Material: VIDRO COMUM LISO VERDE, ALUMÍNIO COM PINTURA ELETROSTÁTICA BRANCA
OverallHeight: 0.57 m; OverallWidth: 1.57 m
Pset_WindowCommon - IsExternal: no; Reference: 150 x 50
Name (Janela 150x1:150 x 50:...)
4265729
4265988
4272831
4273401
4276557
4276841

# IfcWindow: 200 x 110 (2)
In: Nível 1.2
Type - ParameterTakesPrecedence: no; Sizeable: no; Material: VIDRO COMUM LISO VERDE, ALUMÍNIO COM PINTURA ELETROSTÁTICA BRANCA
OverallHeight: 1.17 m; OverallWidth: 2.07 m
Pset_WindowCommon - IsExternal: no; Reference: 200 x 110
Name (Janela 200x110:200 x 110:...)
4274833
4276122

# IfcWindow: 200 x 50 (4)
In: Nível 1.2
Type - ParameterTakesPrecedence: no; Sizeable: no; Material: VIDRO COMUM LISO VERDE, ALUMÍNIO COM PINTURA ELETROSTÁTICA BRANCA
OverallHeight: 0.57 m; OverallWidth: 2.07 m
Pset_WindowCommon - IsExternal: no; Reference: 200 x 50
Name (Janela 200x110:200 x 50:...)
4301449
4301806
4302130
4367618

# IfcWindow: 300 x 50 (5)
In: Nível 1.2
Type - ParameterTakesPrecedence: no; Sizeable: no; Material: VIDRO COMUM LISO VERDE, ALUMÍNIO COM PINTURA ELETROSTÁTICA BRANCA
OverallHeight: 0.57 m; OverallWidth: 3.07 m
Pset_WindowCommon - IsExternal: no; Reference: 300 x 50
Name (Janela 300x110:300 x 50:...)
4367179
4367346
4367571
4367572
4367596

# IfcWindow: Cobogó c1- 1.20 x 0.40/1.0 (2)
In: Nível 1.2
Type - ConstructionType: OTHER_CONSTRUCTION; ParameterTakesPrecedence: no; Sizeable: no; Material: 000B_Cobogó_Cimento
OverallHeight: 0.4 m; OverallWidth: 0.6 m
Pset_WindowCommon - IsExternal: no; Reference: Cobogó c1- 1.20 x 0.40/1.0
Pset_ManufacturerTypeInformation - Manufacturer: Alan Araújo
Name (Cobogó:Cobogó c1- 1.20 x 0.40/1.0:...)
4334233
4334474
